VERSION 5.8 ;
BUSBITCHARS "[]" ;
DIVIDERCHAR "/" ;
UNITS
    DATABASE MICRONS 1000 ;
END UNITS

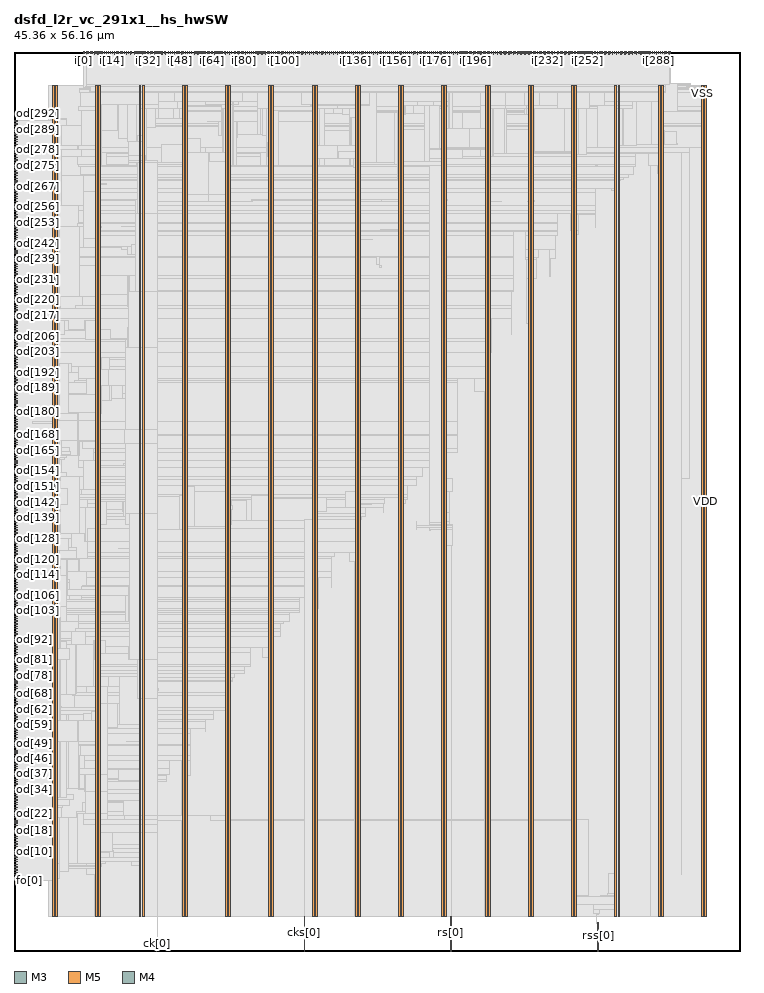
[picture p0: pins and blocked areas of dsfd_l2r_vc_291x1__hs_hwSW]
MACRO dsfd_l2r_vc_291x1__hs_hwSW
  FOREIGN dsfd_l2r_vc_291x1__hs_hwSW 0 0 ;
  CLASS BLOCK ;
  SIZE 45.36 BY 56.16 ;
  PIN ck[0]
    DIRECTION INPUT ;
    USE SIGNAL ;
    PORT
      LAYER M3 ;
        RECT  8.892 0 8.91 0.144 ;
    END
    PORT
      LAYER M3 ;
        RECT  8.892 0.108 8.91 0.52 ;
    END
  END ck[0]
  PIN cks[0]
    DIRECTION INPUT ;
    USE SIGNAL ;
    PORT
      LAYER M5 ;
        RECT  18.096 0 18.12 0.192 ;
    END
    PORT
      LAYER M5 ;
        RECT  18.096 0.144 18.12 2.137 ;
    END
  END cks[0]
  PIN fo[0]
    DIRECTION OUTPUT ;
    USE SIGNAL ;
    PORT
      LAYER M4 ;
        RECT  0 4.416 0.192 4.44 ;
    END
  END fo[0]
  PIN i[0]
    DIRECTION INPUT ;
    USE SIGNAL ;
    PORT
      LAYER M3 ;
        RECT  4.356 56.016 4.374 56.16 ;
    END
  END i[0]
  PIN i[100]
    DIRECTION INPUT ;
    USE SIGNAL ;
    PORT
      LAYER M3 ;
        RECT  16.812 56.016 16.83 56.16 ;
    END
  END i[100]
  PIN i[101]
    DIRECTION INPUT ;
    USE SIGNAL ;
    PORT
      LAYER M5 ;
        RECT  16.944 55.968 16.968 56.16 ;
    END
  END i[101]
  PIN i[102]
    DIRECTION INPUT ;
    USE SIGNAL ;
    PORT
      LAYER M3 ;
        RECT  17.064 56.016 17.082 56.16 ;
    END
  END i[102]
  PIN i[103]
    DIRECTION INPUT ;
    USE SIGNAL ;
    PORT
      LAYER M5 ;
        RECT  17.184 55.968 17.208 56.16 ;
    END
  END i[103]
  PIN i[104]
    DIRECTION INPUT ;
    USE SIGNAL ;
    PORT
      LAYER M3 ;
        RECT  17.316 56.016 17.334 56.16 ;
    END
  END i[104]
  PIN i[105]
    DIRECTION INPUT ;
    USE SIGNAL ;
    PORT
      LAYER M5 ;
        RECT  17.424 55.968 17.448 56.16 ;
    END
  END i[105]
  PIN i[106]
    DIRECTION INPUT ;
    USE SIGNAL ;
    PORT
      LAYER M3 ;
        RECT  17.568 56.016 17.586 56.16 ;
    END
  END i[106]
  PIN i[107]
    DIRECTION INPUT ;
    USE SIGNAL ;
    PORT
      LAYER M5 ;
        RECT  17.712 55.968 17.736 56.16 ;
    END
  END i[107]
  PIN i[108]
    DIRECTION INPUT ;
    USE SIGNAL ;
    PORT
      LAYER M3 ;
        RECT  17.82 56.016 17.838 56.16 ;
    END
  END i[108]
  PIN i[109]
    DIRECTION INPUT ;
    USE SIGNAL ;
    PORT
      LAYER M5 ;
        RECT  17.952 55.968 17.976 56.16 ;
    END
  END i[109]
  PIN i[10]
    DIRECTION INPUT ;
    USE SIGNAL ;
    PORT
      LAYER M3 ;
        RECT  5.616 56.016 5.634 56.16 ;
    END
  END i[10]
  PIN i[110]
    DIRECTION INPUT ;
    USE SIGNAL ;
    PORT
      LAYER M3 ;
        RECT  18.072 56.016 18.09 56.16 ;
    END
  END i[110]
  PIN i[111]
    DIRECTION INPUT ;
    USE SIGNAL ;
    PORT
      LAYER M5 ;
        RECT  18.192 55.968 18.216 56.16 ;
    END
  END i[111]
  PIN i[112]
    DIRECTION INPUT ;
    USE SIGNAL ;
    PORT
      LAYER M3 ;
        RECT  18.324 56.016 18.342 56.16 ;
    END
  END i[112]
  PIN i[113]
    DIRECTION INPUT ;
    USE SIGNAL ;
    PORT
      LAYER M5 ;
        RECT  18.432 55.968 18.456 56.16 ;
    END
  END i[113]
  PIN i[114]
    DIRECTION INPUT ;
    USE SIGNAL ;
    PORT
      LAYER M3 ;
        RECT  18.576 56.016 18.594 56.16 ;
    END
  END i[114]
  PIN i[115]
    DIRECTION INPUT ;
    USE SIGNAL ;
    PORT
      LAYER M5 ;
        RECT  18.672 55.968 18.696 56.16 ;
    END
  END i[115]
  PIN i[116]
    DIRECTION INPUT ;
    USE SIGNAL ;
    PORT
      LAYER M3 ;
        RECT  18.828 56.016 18.846 56.16 ;
    END
  END i[116]
  PIN i[117]
    DIRECTION INPUT ;
    USE SIGNAL ;
    PORT
      LAYER M5 ;
        RECT  18.912 55.968 18.936 56.16 ;
    END
  END i[117]
  PIN i[118]
    DIRECTION INPUT ;
    USE SIGNAL ;
    PORT
      LAYER M3 ;
        RECT  19.044 56.016 19.062 56.16 ;
    END
  END i[118]
  PIN i[119]
    DIRECTION INPUT ;
    USE SIGNAL ;
    PORT
      LAYER M5 ;
        RECT  19.2 55.968 19.224 56.16 ;
    END
  END i[119]
  PIN i[11]
    DIRECTION INPUT ;
    USE SIGNAL ;
    PORT
      LAYER M5 ;
        RECT  5.76 55.968 5.784 56.16 ;
    END
  END i[11]
  PIN i[120]
    DIRECTION INPUT ;
    USE SIGNAL ;
    PORT
      LAYER M3 ;
        RECT  19.296 56.016 19.314 56.16 ;
    END
  END i[120]
  PIN i[121]
    DIRECTION INPUT ;
    USE SIGNAL ;
    PORT
      LAYER M5 ;
        RECT  19.44 55.968 19.464 56.16 ;
    END
  END i[121]
  PIN i[122]
    DIRECTION INPUT ;
    USE SIGNAL ;
    PORT
      LAYER M3 ;
        RECT  19.548 56.016 19.566 56.16 ;
    END
  END i[122]
  PIN i[123]
    DIRECTION INPUT ;
    USE SIGNAL ;
    PORT
      LAYER M5 ;
        RECT  19.68 55.968 19.704 56.16 ;
    END
  END i[123]
  PIN i[124]
    DIRECTION INPUT ;
    USE SIGNAL ;
    PORT
      LAYER M3 ;
        RECT  19.8 56.016 19.818 56.16 ;
    END
  END i[124]
  PIN i[125]
    DIRECTION INPUT ;
    USE SIGNAL ;
    PORT
      LAYER M5 ;
        RECT  19.92 55.968 19.944 56.16 ;
    END
  END i[125]
  PIN i[126]
    DIRECTION INPUT ;
    USE SIGNAL ;
    PORT
      LAYER M3 ;
        RECT  20.052 56.016 20.07 56.16 ;
    END
  END i[126]
  PIN i[127]
    DIRECTION INPUT ;
    USE SIGNAL ;
    PORT
      LAYER M5 ;
        RECT  20.16 55.968 20.184 56.16 ;
    END
  END i[127]
  PIN i[128]
    DIRECTION INPUT ;
    USE SIGNAL ;
    PORT
      LAYER M3 ;
        RECT  20.304 56.016 20.322 56.16 ;
    END
  END i[128]
  PIN i[129]
    DIRECTION INPUT ;
    USE SIGNAL ;
    PORT
      LAYER M5 ;
        RECT  20.448 55.968 20.472 56.16 ;
    END
  END i[129]
  PIN i[12]
    DIRECTION INPUT ;
    USE SIGNAL ;
    PORT
      LAYER M3 ;
        RECT  5.868 56.016 5.886 56.16 ;
    END
  END i[12]
  PIN i[130]
    DIRECTION INPUT ;
    USE SIGNAL ;
    PORT
      LAYER M3 ;
        RECT  20.556 56.016 20.574 56.16 ;
    END
  END i[130]
  PIN i[131]
    DIRECTION INPUT ;
    USE SIGNAL ;
    PORT
      LAYER M5 ;
        RECT  20.688 55.968 20.712 56.16 ;
    END
  END i[131]
  PIN i[132]
    DIRECTION INPUT ;
    USE SIGNAL ;
    PORT
      LAYER M3 ;
        RECT  20.808 56.016 20.826 56.16 ;
    END
  END i[132]
  PIN i[133]
    DIRECTION INPUT ;
    USE SIGNAL ;
    PORT
      LAYER M5 ;
        RECT  20.928 55.968 20.952 56.16 ;
    END
  END i[133]
  PIN i[134]
    DIRECTION INPUT ;
    USE SIGNAL ;
    PORT
      LAYER M3 ;
        RECT  21.06 56.016 21.078 56.16 ;
    END
  END i[134]
  PIN i[135]
    DIRECTION INPUT ;
    USE SIGNAL ;
    PORT
      LAYER M5 ;
        RECT  21.168 55.968 21.192 56.16 ;
    END
  END i[135]
  PIN i[136]
    DIRECTION INPUT ;
    USE SIGNAL ;
    PORT
      LAYER M3 ;
        RECT  21.312 56.016 21.33 56.16 ;
    END
  END i[136]
  PIN i[137]
    DIRECTION INPUT ;
    USE SIGNAL ;
    PORT
      LAYER M5 ;
        RECT  21.408 55.968 21.432 56.16 ;
    END
  END i[137]
  PIN i[138]
    DIRECTION INPUT ;
    USE SIGNAL ;
    PORT
      LAYER M3 ;
        RECT  21.564 56.016 21.582 56.16 ;
    END
  END i[138]
  PIN i[139]
    DIRECTION INPUT ;
    USE SIGNAL ;
    PORT
      LAYER M5 ;
        RECT  21.696 55.968 21.72 56.16 ;
    END
  END i[139]
  PIN i[13]
    DIRECTION INPUT ;
    USE SIGNAL ;
    PORT
      LAYER M5 ;
        RECT  6 55.968 6.024 56.16 ;
    END
  END i[13]
  PIN i[140]
    DIRECTION INPUT ;
    USE SIGNAL ;
    PORT
      LAYER M3 ;
        RECT  21.816 56.016 21.834 56.16 ;
    END
  END i[140]
  PIN i[141]
    DIRECTION INPUT ;
    USE SIGNAL ;
    PORT
      LAYER M5 ;
        RECT  21.936 55.968 21.96 56.16 ;
    END
  END i[141]
  PIN i[142]
    DIRECTION INPUT ;
    USE SIGNAL ;
    PORT
      LAYER M3 ;
        RECT  22.032 56.016 22.05 56.16 ;
    END
  END i[142]
  PIN i[143]
    DIRECTION INPUT ;
    USE SIGNAL ;
    PORT
      LAYER M5 ;
        RECT  22.176 55.968 22.2 56.16 ;
    END
  END i[143]
  PIN i[144]
    DIRECTION INPUT ;
    USE SIGNAL ;
    PORT
      LAYER M3 ;
        RECT  22.284 56.016 22.302 56.16 ;
    END
  END i[144]
  PIN i[145]
    DIRECTION INPUT ;
    USE SIGNAL ;
    PORT
      LAYER M5 ;
        RECT  22.416 55.968 22.44 56.16 ;
    END
  END i[145]
  PIN i[146]
    DIRECTION INPUT ;
    USE SIGNAL ;
    PORT
      LAYER M3 ;
        RECT  22.536 56.016 22.554 56.16 ;
    END
  END i[146]
  PIN i[147]
    DIRECTION INPUT ;
    USE SIGNAL ;
    PORT
      LAYER M5 ;
        RECT  22.656 55.968 22.68 56.16 ;
    END
  END i[147]
  PIN i[148]
    DIRECTION INPUT ;
    USE SIGNAL ;
    PORT
      LAYER M3 ;
        RECT  22.788 56.016 22.806 56.16 ;
    END
  END i[148]
  PIN i[149]
    DIRECTION INPUT ;
    USE SIGNAL ;
    PORT
      LAYER M5 ;
        RECT  22.896 55.968 22.92 56.16 ;
    END
  END i[149]
  PIN i[14]
    DIRECTION INPUT ;
    USE SIGNAL ;
    PORT
      LAYER M3 ;
        RECT  6.12 56.016 6.138 56.16 ;
    END
  END i[14]
  PIN i[150]
    DIRECTION INPUT ;
    USE SIGNAL ;
    PORT
      LAYER M3 ;
        RECT  23.04 56.016 23.058 56.16 ;
    END
  END i[150]
  PIN i[151]
    DIRECTION INPUT ;
    USE SIGNAL ;
    PORT
      LAYER M5 ;
        RECT  23.184 55.968 23.208 56.16 ;
    END
  END i[151]
  PIN i[152]
    DIRECTION INPUT ;
    USE SIGNAL ;
    PORT
      LAYER M3 ;
        RECT  23.292 56.016 23.31 56.16 ;
    END
  END i[152]
  PIN i[153]
    DIRECTION INPUT ;
    USE SIGNAL ;
    PORT
      LAYER M5 ;
        RECT  23.424 55.968 23.448 56.16 ;
    END
  END i[153]
  PIN i[154]
    DIRECTION INPUT ;
    USE SIGNAL ;
    PORT
      LAYER M3 ;
        RECT  23.544 56.016 23.562 56.16 ;
    END
  END i[154]
  PIN i[155]
    DIRECTION INPUT ;
    USE SIGNAL ;
    PORT
      LAYER M5 ;
        RECT  23.664 55.968 23.688 56.16 ;
    END
  END i[155]
  PIN i[156]
    DIRECTION INPUT ;
    USE SIGNAL ;
    PORT
      LAYER M3 ;
        RECT  23.796 56.016 23.814 56.16 ;
    END
  END i[156]
  PIN i[157]
    DIRECTION INPUT ;
    USE SIGNAL ;
    PORT
      LAYER M5 ;
        RECT  23.904 55.968 23.928 56.16 ;
    END
  END i[157]
  PIN i[158]
    DIRECTION INPUT ;
    USE SIGNAL ;
    PORT
      LAYER M3 ;
        RECT  24.048 56.016 24.066 56.16 ;
    END
  END i[158]
  PIN i[159]
    DIRECTION INPUT ;
    USE SIGNAL ;
    PORT
      LAYER M5 ;
        RECT  24.144 55.968 24.168 56.16 ;
    END
  END i[159]
  PIN i[15]
    DIRECTION INPUT ;
    USE SIGNAL ;
    PORT
      LAYER M5 ;
        RECT  6.24 55.968 6.264 56.16 ;
    END
  END i[15]
  PIN i[160]
    DIRECTION INPUT ;
    USE SIGNAL ;
    PORT
      LAYER M3 ;
        RECT  24.3 56.016 24.318 56.16 ;
    END
  END i[160]
  PIN i[161]
    DIRECTION INPUT ;
    USE SIGNAL ;
    PORT
      LAYER M5 ;
        RECT  24.432 55.968 24.456 56.16 ;
    END
  END i[161]
  PIN i[162]
    DIRECTION INPUT ;
    USE SIGNAL ;
    PORT
      LAYER M3 ;
        RECT  24.552 56.016 24.57 56.16 ;
    END
  END i[162]
  PIN i[163]
    DIRECTION INPUT ;
    USE SIGNAL ;
    PORT
      LAYER M5 ;
        RECT  24.672 55.968 24.696 56.16 ;
    END
  END i[163]
  PIN i[164]
    DIRECTION INPUT ;
    USE SIGNAL ;
    PORT
      LAYER M3 ;
        RECT  24.804 56.016 24.822 56.16 ;
    END
  END i[164]
  PIN i[165]
    DIRECTION INPUT ;
    USE SIGNAL ;
    PORT
      LAYER M5 ;
        RECT  24.912 55.968 24.936 56.16 ;
    END
  END i[165]
  PIN i[166]
    DIRECTION INPUT ;
    USE SIGNAL ;
    PORT
      LAYER M3 ;
        RECT  25.02 56.016 25.038 56.16 ;
    END
  END i[166]
  PIN i[167]
    DIRECTION INPUT ;
    USE SIGNAL ;
    PORT
      LAYER M5 ;
        RECT  25.152 55.968 25.176 56.16 ;
    END
  END i[167]
  PIN i[168]
    DIRECTION INPUT ;
    USE SIGNAL ;
    PORT
      LAYER M3 ;
        RECT  25.272 56.016 25.29 56.16 ;
    END
  END i[168]
  PIN i[169]
    DIRECTION INPUT ;
    USE SIGNAL ;
    PORT
      LAYER M5 ;
        RECT  25.392 55.968 25.416 56.16 ;
    END
  END i[169]
  PIN i[16]
    DIRECTION INPUT ;
    USE SIGNAL ;
    PORT
      LAYER M3 ;
        RECT  6.372 56.016 6.39 56.16 ;
    END
  END i[16]
  PIN i[170]
    DIRECTION INPUT ;
    USE SIGNAL ;
    PORT
      LAYER M3 ;
        RECT  25.524 56.016 25.542 56.16 ;
    END
  END i[170]
  PIN i[171]
    DIRECTION INPUT ;
    USE SIGNAL ;
    PORT
      LAYER M5 ;
        RECT  25.632 55.968 25.656 56.16 ;
    END
  END i[171]
  PIN i[172]
    DIRECTION INPUT ;
    USE SIGNAL ;
    PORT
      LAYER M3 ;
        RECT  25.776 56.016 25.794 56.16 ;
    END
  END i[172]
  PIN i[173]
    DIRECTION INPUT ;
    USE SIGNAL ;
    PORT
      LAYER M5 ;
        RECT  25.92 55.968 25.944 56.16 ;
    END
  END i[173]
  PIN i[174]
    DIRECTION INPUT ;
    USE SIGNAL ;
    PORT
      LAYER M3 ;
        RECT  26.028 56.016 26.046 56.16 ;
    END
  END i[174]
  PIN i[175]
    DIRECTION INPUT ;
    USE SIGNAL ;
    PORT
      LAYER M5 ;
        RECT  26.16 55.968 26.184 56.16 ;
    END
  END i[175]
  PIN i[176]
    DIRECTION INPUT ;
    USE SIGNAL ;
    PORT
      LAYER M3 ;
        RECT  26.28 56.016 26.298 56.16 ;
    END
  END i[176]
  PIN i[177]
    DIRECTION INPUT ;
    USE SIGNAL ;
    PORT
      LAYER M5 ;
        RECT  26.4 55.968 26.424 56.16 ;
    END
  END i[177]
  PIN i[178]
    DIRECTION INPUT ;
    USE SIGNAL ;
    PORT
      LAYER M3 ;
        RECT  26.532 56.016 26.55 56.16 ;
    END
  END i[178]
  PIN i[179]
    DIRECTION INPUT ;
    USE SIGNAL ;
    PORT
      LAYER M5 ;
        RECT  26.64 55.968 26.664 56.16 ;
    END
  END i[179]
  PIN i[17]
    DIRECTION INPUT ;
    USE SIGNAL ;
    PORT
      LAYER M5 ;
        RECT  6.48 55.968 6.504 56.16 ;
    END
  END i[17]
  PIN i[180]
    DIRECTION INPUT ;
    USE SIGNAL ;
    PORT
      LAYER M3 ;
        RECT  26.784 56.016 26.802 56.16 ;
    END
  END i[180]
  PIN i[181]
    DIRECTION INPUT ;
    USE SIGNAL ;
    PORT
      LAYER M5 ;
        RECT  26.88 55.968 26.904 56.16 ;
    END
  END i[181]
  PIN i[182]
    DIRECTION INPUT ;
    USE SIGNAL ;
    PORT
      LAYER M3 ;
        RECT  27.036 56.016 27.054 56.16 ;
    END
  END i[182]
  PIN i[183]
    DIRECTION INPUT ;
    USE SIGNAL ;
    PORT
      LAYER M5 ;
        RECT  27.168 55.968 27.192 56.16 ;
    END
  END i[183]
  PIN i[184]
    DIRECTION INPUT ;
    USE SIGNAL ;
    PORT
      LAYER M3 ;
        RECT  27.288 56.016 27.306 56.16 ;
    END
  END i[184]
  PIN i[185]
    DIRECTION INPUT ;
    USE SIGNAL ;
    PORT
      LAYER M5 ;
        RECT  27.408 55.968 27.432 56.16 ;
    END
  END i[185]
  PIN i[186]
    DIRECTION INPUT ;
    USE SIGNAL ;
    PORT
      LAYER M3 ;
        RECT  27.54 56.016 27.558 56.16 ;
    END
  END i[186]
  PIN i[187]
    DIRECTION INPUT ;
    USE SIGNAL ;
    PORT
      LAYER M5 ;
        RECT  27.648 55.968 27.672 56.16 ;
    END
  END i[187]
  PIN i[188]
    DIRECTION INPUT ;
    USE SIGNAL ;
    PORT
      LAYER M3 ;
        RECT  27.792 56.016 27.81 56.16 ;
    END
  END i[188]
  PIN i[189]
    DIRECTION INPUT ;
    USE SIGNAL ;
    PORT
      LAYER M5 ;
        RECT  27.888 55.968 27.912 56.16 ;
    END
  END i[189]
  PIN i[18]
    DIRECTION INPUT ;
    USE SIGNAL ;
    PORT
      LAYER M3 ;
        RECT  6.624 56.016 6.642 56.16 ;
    END
  END i[18]
  PIN i[190]
    DIRECTION INPUT ;
    USE SIGNAL ;
    PORT
      LAYER M3 ;
        RECT  28.008 56.016 28.026 56.16 ;
    END
  END i[190]
  PIN i[191]
    DIRECTION INPUT ;
    USE SIGNAL ;
    PORT
      LAYER M5 ;
        RECT  28.128 55.968 28.152 56.16 ;
    END
  END i[191]
  PIN i[192]
    DIRECTION INPUT ;
    USE SIGNAL ;
    PORT
      LAYER M3 ;
        RECT  28.26 56.016 28.278 56.16 ;
    END
  END i[192]
  PIN i[193]
    DIRECTION INPUT ;
    USE SIGNAL ;
    PORT
      LAYER M5 ;
        RECT  28.416 55.968 28.44 56.16 ;
    END
  END i[193]
  PIN i[194]
    DIRECTION INPUT ;
    USE SIGNAL ;
    PORT
      LAYER M3 ;
        RECT  28.512 56.016 28.53 56.16 ;
    END
  END i[194]
  PIN i[195]
    DIRECTION INPUT ;
    USE SIGNAL ;
    PORT
      LAYER M5 ;
        RECT  28.656 55.968 28.68 56.16 ;
    END
  END i[195]
  PIN i[196]
    DIRECTION INPUT ;
    USE SIGNAL ;
    PORT
      LAYER M3 ;
        RECT  28.764 56.016 28.782 56.16 ;
    END
  END i[196]
  PIN i[197]
    DIRECTION INPUT ;
    USE SIGNAL ;
    PORT
      LAYER M5 ;
        RECT  28.896 55.968 28.92 56.16 ;
    END
  END i[197]
  PIN i[198]
    DIRECTION INPUT ;
    USE SIGNAL ;
    PORT
      LAYER M3 ;
        RECT  29.016 56.016 29.034 56.16 ;
    END
  END i[198]
  PIN i[199]
    DIRECTION INPUT ;
    USE SIGNAL ;
    PORT
      LAYER M5 ;
        RECT  29.136 55.968 29.16 56.16 ;
    END
  END i[199]
  PIN i[19]
    DIRECTION INPUT ;
    USE SIGNAL ;
    PORT
      LAYER M5 ;
        RECT  6.72 55.968 6.744 56.16 ;
    END
  END i[19]
  PIN i[1]
    DIRECTION INPUT ;
    USE SIGNAL ;
    PORT
      LAYER M5 ;
        RECT  4.512 55.968 4.536 56.16 ;
    END
  END i[1]
  PIN i[200]
    DIRECTION INPUT ;
    USE SIGNAL ;
    PORT
      LAYER M3 ;
        RECT  29.268 56.016 29.286 56.16 ;
    END
  END i[200]
  PIN i[201]
    DIRECTION INPUT ;
    USE SIGNAL ;
    PORT
      LAYER M5 ;
        RECT  29.376 55.968 29.4 56.16 ;
    END
  END i[201]
  PIN i[202]
    DIRECTION INPUT ;
    USE SIGNAL ;
    PORT
      LAYER M3 ;
        RECT  29.52 56.016 29.538 56.16 ;
    END
  END i[202]
  PIN i[203]
    DIRECTION INPUT ;
    USE SIGNAL ;
    PORT
      LAYER M5 ;
        RECT  29.616 55.968 29.64 56.16 ;
    END
  END i[203]
  PIN i[204]
    DIRECTION INPUT ;
    USE SIGNAL ;
    PORT
      LAYER M3 ;
        RECT  29.772 56.016 29.79 56.16 ;
    END
  END i[204]
  PIN i[205]
    DIRECTION INPUT ;
    USE SIGNAL ;
    PORT
      LAYER M5 ;
        RECT  29.904 55.968 29.928 56.16 ;
    END
  END i[205]
  PIN i[206]
    DIRECTION INPUT ;
    USE SIGNAL ;
    PORT
      LAYER M3 ;
        RECT  30.024 56.016 30.042 56.16 ;
    END
  END i[206]
  PIN i[207]
    DIRECTION INPUT ;
    USE SIGNAL ;
    PORT
      LAYER M5 ;
        RECT  30.144 55.968 30.168 56.16 ;
    END
  END i[207]
  PIN i[208]
    DIRECTION INPUT ;
    USE SIGNAL ;
    PORT
      LAYER M3 ;
        RECT  30.276 56.016 30.294 56.16 ;
    END
  END i[208]
  PIN i[209]
    DIRECTION INPUT ;
    USE SIGNAL ;
    PORT
      LAYER M5 ;
        RECT  30.384 55.968 30.408 56.16 ;
    END
  END i[209]
  PIN i[20]
    DIRECTION INPUT ;
    USE SIGNAL ;
    PORT
      LAYER M3 ;
        RECT  6.876 56.016 6.894 56.16 ;
    END
  END i[20]
  PIN i[210]
    DIRECTION INPUT ;
    USE SIGNAL ;
    PORT
      LAYER M3 ;
        RECT  30.528 56.016 30.546 56.16 ;
    END
  END i[210]
  PIN i[211]
    DIRECTION INPUT ;
    USE SIGNAL ;
    PORT
      LAYER M5 ;
        RECT  30.624 55.968 30.648 56.16 ;
    END
  END i[211]
  PIN i[212]
    DIRECTION INPUT ;
    USE SIGNAL ;
    PORT
      LAYER M3 ;
        RECT  30.744 56.016 30.762 56.16 ;
    END
  END i[212]
  PIN i[213]
    DIRECTION INPUT ;
    USE SIGNAL ;
    PORT
      LAYER M5 ;
        RECT  30.864 55.968 30.888 56.16 ;
    END
  END i[213]
  PIN i[214]
    DIRECTION INPUT ;
    USE SIGNAL ;
    PORT
      LAYER M3 ;
        RECT  30.996 56.016 31.014 56.16 ;
    END
  END i[214]
  PIN i[215]
    DIRECTION INPUT ;
    USE SIGNAL ;
    PORT
      LAYER M5 ;
        RECT  31.152 55.968 31.176 56.16 ;
    END
  END i[215]
  PIN i[216]
    DIRECTION INPUT ;
    USE SIGNAL ;
    PORT
      LAYER M3 ;
        RECT  31.248 56.016 31.266 56.16 ;
    END
  END i[216]
  PIN i[217]
    DIRECTION INPUT ;
    USE SIGNAL ;
    PORT
      LAYER M5 ;
        RECT  31.392 55.968 31.416 56.16 ;
    END
  END i[217]
  PIN i[218]
    DIRECTION INPUT ;
    USE SIGNAL ;
    PORT
      LAYER M3 ;
        RECT  31.5 56.016 31.518 56.16 ;
    END
  END i[218]
  PIN i[219]
    DIRECTION INPUT ;
    USE SIGNAL ;
    PORT
      LAYER M5 ;
        RECT  31.632 55.968 31.656 56.16 ;
    END
  END i[219]
  PIN i[21]
    DIRECTION INPUT ;
    USE SIGNAL ;
    PORT
      LAYER M5 ;
        RECT  7.008 55.968 7.032 56.16 ;
    END
  END i[21]
  PIN i[220]
    DIRECTION INPUT ;
    USE SIGNAL ;
    PORT
      LAYER M3 ;
        RECT  31.752 56.016 31.77 56.16 ;
    END
  END i[220]
  PIN i[221]
    DIRECTION INPUT ;
    USE SIGNAL ;
    PORT
      LAYER M5 ;
        RECT  31.872 55.968 31.896 56.16 ;
    END
  END i[221]
  PIN i[222]
    DIRECTION INPUT ;
    USE SIGNAL ;
    PORT
      LAYER M3 ;
        RECT  32.004 56.016 32.022 56.16 ;
    END
  END i[222]
  PIN i[223]
    DIRECTION INPUT ;
    USE SIGNAL ;
    PORT
      LAYER M5 ;
        RECT  32.112 55.968 32.136 56.16 ;
    END
  END i[223]
  PIN i[224]
    DIRECTION INPUT ;
    USE SIGNAL ;
    PORT
      LAYER M3 ;
        RECT  32.256 56.016 32.274 56.16 ;
    END
  END i[224]
  PIN i[225]
    DIRECTION INPUT ;
    USE SIGNAL ;
    PORT
      LAYER M5 ;
        RECT  32.4 55.968 32.424 56.16 ;
    END
  END i[225]
  PIN i[226]
    DIRECTION INPUT ;
    USE SIGNAL ;
    PORT
      LAYER M3 ;
        RECT  32.508 56.016 32.526 56.16 ;
    END
  END i[226]
  PIN i[227]
    DIRECTION INPUT ;
    USE SIGNAL ;
    PORT
      LAYER M5 ;
        RECT  32.64 55.968 32.664 56.16 ;
    END
  END i[227]
  PIN i[228]
    DIRECTION INPUT ;
    USE SIGNAL ;
    PORT
      LAYER M3 ;
        RECT  32.76 56.016 32.778 56.16 ;
    END
  END i[228]
  PIN i[229]
    DIRECTION INPUT ;
    USE SIGNAL ;
    PORT
      LAYER M5 ;
        RECT  32.88 55.968 32.904 56.16 ;
    END
  END i[229]
  PIN i[22]
    DIRECTION INPUT ;
    USE SIGNAL ;
    PORT
      LAYER M3 ;
        RECT  7.128 56.016 7.146 56.16 ;
    END
  END i[22]
  PIN i[230]
    DIRECTION INPUT ;
    USE SIGNAL ;
    PORT
      LAYER M3 ;
        RECT  33.012 56.016 33.03 56.16 ;
    END
  END i[230]
  PIN i[231]
    DIRECTION INPUT ;
    USE SIGNAL ;
    PORT
      LAYER M5 ;
        RECT  33.12 55.968 33.144 56.16 ;
    END
  END i[231]
  PIN i[232]
    DIRECTION INPUT ;
    USE SIGNAL ;
    PORT
      LAYER M3 ;
        RECT  33.264 56.016 33.282 56.16 ;
    END
  END i[232]
  PIN i[233]
    DIRECTION INPUT ;
    USE SIGNAL ;
    PORT
      LAYER M5 ;
        RECT  33.36 55.968 33.384 56.16 ;
    END
  END i[233]
  PIN i[234]
    DIRECTION INPUT ;
    USE SIGNAL ;
    PORT
      LAYER M3 ;
        RECT  33.516 56.016 33.534 56.16 ;
    END
  END i[234]
  PIN i[235]
    DIRECTION INPUT ;
    USE SIGNAL ;
    PORT
      LAYER M5 ;
        RECT  33.6 55.968 33.624 56.16 ;
    END
  END i[235]
  PIN i[236]
    DIRECTION INPUT ;
    USE SIGNAL ;
    PORT
      LAYER M3 ;
        RECT  33.732 56.016 33.75 56.16 ;
    END
  END i[236]
  PIN i[237]
    DIRECTION INPUT ;
    USE SIGNAL ;
    PORT
      LAYER M5 ;
        RECT  33.888 55.968 33.912 56.16 ;
    END
  END i[237]
  PIN i[238]
    DIRECTION INPUT ;
    USE SIGNAL ;
    PORT
      LAYER M3 ;
        RECT  33.984 56.016 34.002 56.16 ;
    END
  END i[238]
  PIN i[239]
    DIRECTION INPUT ;
    USE SIGNAL ;
    PORT
      LAYER M5 ;
        RECT  34.128 55.968 34.152 56.16 ;
    END
  END i[239]
  PIN i[23]
    DIRECTION INPUT ;
    USE SIGNAL ;
    PORT
      LAYER M5 ;
        RECT  7.248 55.968 7.272 56.16 ;
    END
  END i[23]
  PIN i[240]
    DIRECTION INPUT ;
    USE SIGNAL ;
    PORT
      LAYER M3 ;
        RECT  34.236 56.016 34.254 56.16 ;
    END
  END i[240]
  PIN i[241]
    DIRECTION INPUT ;
    USE SIGNAL ;
    PORT
      LAYER M5 ;
        RECT  34.368 55.968 34.392 56.16 ;
    END
  END i[241]
  PIN i[242]
    DIRECTION INPUT ;
    USE SIGNAL ;
    PORT
      LAYER M3 ;
        RECT  34.488 56.016 34.506 56.16 ;
    END
  END i[242]
  PIN i[243]
    DIRECTION INPUT ;
    USE SIGNAL ;
    PORT
      LAYER M5 ;
        RECT  34.608 55.968 34.632 56.16 ;
    END
  END i[243]
  PIN i[244]
    DIRECTION INPUT ;
    USE SIGNAL ;
    PORT
      LAYER M3 ;
        RECT  34.74 56.016 34.758 56.16 ;
    END
  END i[244]
  PIN i[245]
    DIRECTION INPUT ;
    USE SIGNAL ;
    PORT
      LAYER M5 ;
        RECT  34.848 55.968 34.872 56.16 ;
    END
  END i[245]
  PIN i[246]
    DIRECTION INPUT ;
    USE SIGNAL ;
    PORT
      LAYER M3 ;
        RECT  34.992 56.016 35.01 56.16 ;
    END
  END i[246]
  PIN i[247]
    DIRECTION INPUT ;
    USE SIGNAL ;
    PORT
      LAYER M5 ;
        RECT  35.136 55.968 35.16 56.16 ;
    END
  END i[247]
  PIN i[248]
    DIRECTION INPUT ;
    USE SIGNAL ;
    PORT
      LAYER M3 ;
        RECT  35.244 56.016 35.262 56.16 ;
    END
  END i[248]
  PIN i[249]
    DIRECTION INPUT ;
    USE SIGNAL ;
    PORT
      LAYER M5 ;
        RECT  35.376 55.968 35.4 56.16 ;
    END
  END i[249]
  PIN i[24]
    DIRECTION INPUT ;
    USE SIGNAL ;
    PORT
      LAYER M3 ;
        RECT  7.344 56.016 7.362 56.16 ;
    END
  END i[24]
  PIN i[250]
    DIRECTION INPUT ;
    USE SIGNAL ;
    PORT
      LAYER M3 ;
        RECT  35.496 56.016 35.514 56.16 ;
    END
  END i[250]
  PIN i[251]
    DIRECTION INPUT ;
    USE SIGNAL ;
    PORT
      LAYER M5 ;
        RECT  35.616 55.968 35.64 56.16 ;
    END
  END i[251]
  PIN i[252]
    DIRECTION INPUT ;
    USE SIGNAL ;
    PORT
      LAYER M3 ;
        RECT  35.748 56.016 35.766 56.16 ;
    END
  END i[252]
  PIN i[253]
    DIRECTION INPUT ;
    USE SIGNAL ;
    PORT
      LAYER M5 ;
        RECT  35.856 55.968 35.88 56.16 ;
    END
  END i[253]
  PIN i[254]
    DIRECTION INPUT ;
    USE SIGNAL ;
    PORT
      LAYER M3 ;
        RECT  36 56.016 36.018 56.16 ;
    END
  END i[254]
  PIN i[255]
    DIRECTION INPUT ;
    USE SIGNAL ;
    PORT
      LAYER M5 ;
        RECT  36.096 55.968 36.12 56.16 ;
    END
  END i[255]
  PIN i[256]
    DIRECTION INPUT ;
    USE SIGNAL ;
    PORT
      LAYER M3 ;
        RECT  36.252 56.016 36.27 56.16 ;
    END
  END i[256]
  PIN i[257]
    DIRECTION INPUT ;
    USE SIGNAL ;
    PORT
      LAYER M5 ;
        RECT  36.384 55.968 36.408 56.16 ;
    END
  END i[257]
  PIN i[258]
    DIRECTION INPUT ;
    USE SIGNAL ;
    PORT
      LAYER M3 ;
        RECT  36.504 56.016 36.522 56.16 ;
    END
  END i[258]
  PIN i[259]
    DIRECTION INPUT ;
    USE SIGNAL ;
    PORT
      LAYER M5 ;
        RECT  36.624 55.968 36.648 56.16 ;
    END
  END i[259]
  PIN i[25]
    DIRECTION INPUT ;
    USE SIGNAL ;
    PORT
      LAYER M5 ;
        RECT  7.488 55.968 7.512 56.16 ;
    END
  END i[25]
  PIN i[260]
    DIRECTION INPUT ;
    USE SIGNAL ;
    PORT
      LAYER M3 ;
        RECT  36.72 56.016 36.738 56.16 ;
    END
  END i[260]
  PIN i[261]
    DIRECTION INPUT ;
    USE SIGNAL ;
    PORT
      LAYER M5 ;
        RECT  36.864 55.968 36.888 56.16 ;
    END
  END i[261]
  PIN i[262]
    DIRECTION INPUT ;
    USE SIGNAL ;
    PORT
      LAYER M3 ;
        RECT  36.972 56.016 36.99 56.16 ;
    END
  END i[262]
  PIN i[263]
    DIRECTION INPUT ;
    USE SIGNAL ;
    PORT
      LAYER M5 ;
        RECT  37.104 55.968 37.128 56.16 ;
    END
  END i[263]
  PIN i[264]
    DIRECTION INPUT ;
    USE SIGNAL ;
    PORT
      LAYER M3 ;
        RECT  37.224 56.016 37.242 56.16 ;
    END
  END i[264]
  PIN i[265]
    DIRECTION INPUT ;
    USE SIGNAL ;
    PORT
      LAYER M5 ;
        RECT  37.344 55.968 37.368 56.16 ;
    END
  END i[265]
  PIN i[266]
    DIRECTION INPUT ;
    USE SIGNAL ;
    PORT
      LAYER M3 ;
        RECT  37.476 56.016 37.494 56.16 ;
    END
  END i[266]
  PIN i[267]
    DIRECTION INPUT ;
    USE SIGNAL ;
    PORT
      LAYER M5 ;
        RECT  37.584 55.968 37.608 56.16 ;
    END
  END i[267]
  PIN i[268]
    DIRECTION INPUT ;
    USE SIGNAL ;
    PORT
      LAYER M3 ;
        RECT  37.728 56.016 37.746 56.16 ;
    END
  END i[268]
  PIN i[269]
    DIRECTION INPUT ;
    USE SIGNAL ;
    PORT
      LAYER M5 ;
        RECT  37.872 55.968 37.896 56.16 ;
    END
  END i[269]
  PIN i[26]
    DIRECTION INPUT ;
    USE SIGNAL ;
    PORT
      LAYER M3 ;
        RECT  7.596 56.016 7.614 56.16 ;
    END
  END i[26]
  PIN i[270]
    DIRECTION INPUT ;
    USE SIGNAL ;
    PORT
      LAYER M3 ;
        RECT  37.98 56.016 37.998 56.16 ;
    END
  END i[270]
  PIN i[271]
    DIRECTION INPUT ;
    USE SIGNAL ;
    PORT
      LAYER M5 ;
        RECT  38.112 55.968 38.136 56.16 ;
    END
  END i[271]
  PIN i[272]
    DIRECTION INPUT ;
    USE SIGNAL ;
    PORT
      LAYER M3 ;
        RECT  38.232 56.016 38.25 56.16 ;
    END
  END i[272]
  PIN i[273]
    DIRECTION INPUT ;
    USE SIGNAL ;
    PORT
      LAYER M5 ;
        RECT  38.352 55.968 38.376 56.16 ;
    END
  END i[273]
  PIN i[274]
    DIRECTION INPUT ;
    USE SIGNAL ;
    PORT
      LAYER M3 ;
        RECT  38.484 56.016 38.502 56.16 ;
    END
  END i[274]
  PIN i[275]
    DIRECTION INPUT ;
    USE SIGNAL ;
    PORT
      LAYER M5 ;
        RECT  38.592 55.968 38.616 56.16 ;
    END
  END i[275]
  PIN i[276]
    DIRECTION INPUT ;
    USE SIGNAL ;
    PORT
      LAYER M3 ;
        RECT  38.736 56.016 38.754 56.16 ;
    END
  END i[276]
  PIN i[277]
    DIRECTION INPUT ;
    USE SIGNAL ;
    PORT
      LAYER M5 ;
        RECT  38.832 55.968 38.856 56.16 ;
    END
  END i[277]
  PIN i[278]
    DIRECTION INPUT ;
    USE SIGNAL ;
    PORT
      LAYER M3 ;
        RECT  38.988 56.016 39.006 56.16 ;
    END
  END i[278]
  PIN i[279]
    DIRECTION INPUT ;
    USE SIGNAL ;
    PORT
      LAYER M5 ;
        RECT  39.12 55.968 39.144 56.16 ;
    END
  END i[279]
  PIN i[27]
    DIRECTION INPUT ;
    USE SIGNAL ;
    PORT
      LAYER M5 ;
        RECT  7.728 55.968 7.752 56.16 ;
    END
  END i[27]
  PIN i[280]
    DIRECTION INPUT ;
    USE SIGNAL ;
    PORT
      LAYER M3 ;
        RECT  39.24 56.016 39.258 56.16 ;
    END
  END i[280]
  PIN i[281]
    DIRECTION INPUT ;
    USE SIGNAL ;
    PORT
      LAYER M5 ;
        RECT  39.36 55.968 39.384 56.16 ;
    END
  END i[281]
  PIN i[282]
    DIRECTION INPUT ;
    USE SIGNAL ;
    PORT
      LAYER M3 ;
        RECT  39.492 56.016 39.51 56.16 ;
    END
  END i[282]
  PIN i[283]
    DIRECTION INPUT ;
    USE SIGNAL ;
    PORT
      LAYER M5 ;
        RECT  39.6 55.968 39.624 56.16 ;
    END
  END i[283]
  PIN i[284]
    DIRECTION INPUT ;
    USE SIGNAL ;
    PORT
      LAYER M3 ;
        RECT  39.708 56.016 39.726 56.16 ;
    END
  END i[284]
  PIN i[285]
    DIRECTION INPUT ;
    USE SIGNAL ;
    PORT
      LAYER M5 ;
        RECT  39.84 55.968 39.864 56.16 ;
    END
  END i[285]
  PIN i[286]
    DIRECTION INPUT ;
    USE SIGNAL ;
    PORT
      LAYER M3 ;
        RECT  39.96 56.016 39.978 56.16 ;
    END
  END i[286]
  PIN i[287]
    DIRECTION INPUT ;
    USE SIGNAL ;
    PORT
      LAYER M5 ;
        RECT  40.08 55.968 40.104 56.16 ;
    END
  END i[287]
  PIN i[288]
    DIRECTION INPUT ;
    USE SIGNAL ;
    PORT
      LAYER M3 ;
        RECT  40.212 56.016 40.23 56.16 ;
    END
  END i[288]
  PIN i[289]
    DIRECTION INPUT ;
    USE SIGNAL ;
    PORT
      LAYER M5 ;
        RECT  40.32 55.968 40.344 56.16 ;
    END
  END i[289]
  PIN i[28]
    DIRECTION INPUT ;
    USE SIGNAL ;
    PORT
      LAYER M3 ;
        RECT  7.848 56.016 7.866 56.16 ;
    END
  END i[28]
  PIN i[290]
    DIRECTION INPUT ;
    USE SIGNAL ;
    PORT
      LAYER M3 ;
        RECT  40.464 56.016 40.482 56.16 ;
    END
  END i[290]
  PIN i[291]
    DIRECTION INPUT ;
    USE SIGNAL ;
    PORT
      LAYER M5 ;
        RECT  40.608 55.968 40.632 56.16 ;
    END
  END i[291]
  PIN i[29]
    DIRECTION INPUT ;
    USE SIGNAL ;
    PORT
      LAYER M5 ;
        RECT  7.968 55.968 7.992 56.16 ;
    END
  END i[29]
  PIN i[2]
    DIRECTION INPUT ;
    USE SIGNAL ;
    PORT
      LAYER M3 ;
        RECT  4.608 56.016 4.626 56.16 ;
    END
  END i[2]
  PIN i[30]
    DIRECTION INPUT ;
    USE SIGNAL ;
    PORT
      LAYER M3 ;
        RECT  8.1 56.016 8.118 56.16 ;
    END
  END i[30]
  PIN i[31]
    DIRECTION INPUT ;
    USE SIGNAL ;
    PORT
      LAYER M5 ;
        RECT  8.208 55.968 8.232 56.16 ;
    END
  END i[31]
  PIN i[32]
    DIRECTION INPUT ;
    USE SIGNAL ;
    PORT
      LAYER M3 ;
        RECT  8.352 56.016 8.37 56.16 ;
    END
  END i[32]
  PIN i[33]
    DIRECTION INPUT ;
    USE SIGNAL ;
    PORT
      LAYER M5 ;
        RECT  8.496 55.968 8.52 56.16 ;
    END
  END i[33]
  PIN i[34]
    DIRECTION INPUT ;
    USE SIGNAL ;
    PORT
      LAYER M3 ;
        RECT  8.604 56.016 8.622 56.16 ;
    END
  END i[34]
  PIN i[35]
    DIRECTION INPUT ;
    USE SIGNAL ;
    PORT
      LAYER M5 ;
        RECT  8.736 55.968 8.76 56.16 ;
    END
  END i[35]
  PIN i[36]
    DIRECTION INPUT ;
    USE SIGNAL ;
    PORT
      LAYER M3 ;
        RECT  8.856 56.016 8.874 56.16 ;
    END
  END i[36]
  PIN i[37]
    DIRECTION INPUT ;
    USE SIGNAL ;
    PORT
      LAYER M5 ;
        RECT  8.976 55.968 9 56.16 ;
    END
  END i[37]
  PIN i[38]
    DIRECTION INPUT ;
    USE SIGNAL ;
    PORT
      LAYER M3 ;
        RECT  9.108 56.016 9.126 56.16 ;
    END
  END i[38]
  PIN i[39]
    DIRECTION INPUT ;
    USE SIGNAL ;
    PORT
      LAYER M5 ;
        RECT  9.216 55.968 9.24 56.16 ;
    END
  END i[39]
  PIN i[3]
    DIRECTION INPUT ;
    USE SIGNAL ;
    PORT
      LAYER M5 ;
        RECT  4.752 55.968 4.776 56.16 ;
    END
  END i[3]
  PIN i[40]
    DIRECTION INPUT ;
    USE SIGNAL ;
    PORT
      LAYER M3 ;
        RECT  9.36 56.016 9.378 56.16 ;
    END
  END i[40]
  PIN i[41]
    DIRECTION INPUT ;
    USE SIGNAL ;
    PORT
      LAYER M5 ;
        RECT  9.456 55.968 9.48 56.16 ;
    END
  END i[41]
  PIN i[42]
    DIRECTION INPUT ;
    USE SIGNAL ;
    PORT
      LAYER M3 ;
        RECT  9.612 56.016 9.63 56.16 ;
    END
  END i[42]
  PIN i[43]
    DIRECTION INPUT ;
    USE SIGNAL ;
    PORT
      LAYER M5 ;
        RECT  9.744 55.968 9.768 56.16 ;
    END
  END i[43]
  PIN i[44]
    DIRECTION INPUT ;
    USE SIGNAL ;
    PORT
      LAYER M3 ;
        RECT  9.864 56.016 9.882 56.16 ;
    END
  END i[44]
  PIN i[45]
    DIRECTION INPUT ;
    USE SIGNAL ;
    PORT
      LAYER M5 ;
        RECT  9.984 55.968 10.008 56.16 ;
    END
  END i[45]
  PIN i[46]
    DIRECTION INPUT ;
    USE SIGNAL ;
    PORT
      LAYER M3 ;
        RECT  10.116 56.016 10.134 56.16 ;
    END
  END i[46]
  PIN i[47]
    DIRECTION INPUT ;
    USE SIGNAL ;
    PORT
      LAYER M5 ;
        RECT  10.224 55.968 10.248 56.16 ;
    END
  END i[47]
  PIN i[48]
    DIRECTION INPUT ;
    USE SIGNAL ;
    PORT
      LAYER M3 ;
        RECT  10.332 56.016 10.35 56.16 ;
    END
  END i[48]
  PIN i[49]
    DIRECTION INPUT ;
    USE SIGNAL ;
    PORT
      LAYER M5 ;
        RECT  10.464 55.968 10.488 56.16 ;
    END
  END i[49]
  PIN i[4]
    DIRECTION INPUT ;
    USE SIGNAL ;
    PORT
      LAYER M3 ;
        RECT  4.86 56.016 4.878 56.16 ;
    END
  END i[4]
  PIN i[50]
    DIRECTION INPUT ;
    USE SIGNAL ;
    PORT
      LAYER M3 ;
        RECT  10.584 56.016 10.602 56.16 ;
    END
  END i[50]
  PIN i[51]
    DIRECTION INPUT ;
    USE SIGNAL ;
    PORT
      LAYER M5 ;
        RECT  10.704 55.968 10.728 56.16 ;
    END
  END i[51]
  PIN i[52]
    DIRECTION INPUT ;
    USE SIGNAL ;
    PORT
      LAYER M3 ;
        RECT  10.836 56.016 10.854 56.16 ;
    END
  END i[52]
  PIN i[53]
    DIRECTION INPUT ;
    USE SIGNAL ;
    PORT
      LAYER M5 ;
        RECT  10.944 55.968 10.968 56.16 ;
    END
  END i[53]
  PIN i[54]
    DIRECTION INPUT ;
    USE SIGNAL ;
    PORT
      LAYER M3 ;
        RECT  11.088 56.016 11.106 56.16 ;
    END
  END i[54]
  PIN i[55]
    DIRECTION INPUT ;
    USE SIGNAL ;
    PORT
      LAYER M5 ;
        RECT  11.232 55.968 11.256 56.16 ;
    END
  END i[55]
  PIN i[56]
    DIRECTION INPUT ;
    USE SIGNAL ;
    PORT
      LAYER M3 ;
        RECT  11.34 56.016 11.358 56.16 ;
    END
  END i[56]
  PIN i[57]
    DIRECTION INPUT ;
    USE SIGNAL ;
    PORT
      LAYER M5 ;
        RECT  11.472 55.968 11.496 56.16 ;
    END
  END i[57]
  PIN i[58]
    DIRECTION INPUT ;
    USE SIGNAL ;
    PORT
      LAYER M3 ;
        RECT  11.592 56.016 11.61 56.16 ;
    END
  END i[58]
  PIN i[59]
    DIRECTION INPUT ;
    USE SIGNAL ;
    PORT
      LAYER M5 ;
        RECT  11.712 55.968 11.736 56.16 ;
    END
  END i[59]
  PIN i[5]
    DIRECTION INPUT ;
    USE SIGNAL ;
    PORT
      LAYER M5 ;
        RECT  4.992 55.968 5.016 56.16 ;
    END
  END i[5]
  PIN i[60]
    DIRECTION INPUT ;
    USE SIGNAL ;
    PORT
      LAYER M3 ;
        RECT  11.844 56.016 11.862 56.16 ;
    END
  END i[60]
  PIN i[61]
    DIRECTION INPUT ;
    USE SIGNAL ;
    PORT
      LAYER M5 ;
        RECT  11.952 55.968 11.976 56.16 ;
    END
  END i[61]
  PIN i[62]
    DIRECTION INPUT ;
    USE SIGNAL ;
    PORT
      LAYER M3 ;
        RECT  12.096 56.016 12.114 56.16 ;
    END
  END i[62]
  PIN i[63]
    DIRECTION INPUT ;
    USE SIGNAL ;
    PORT
      LAYER M5 ;
        RECT  12.192 55.968 12.216 56.16 ;
    END
  END i[63]
  PIN i[64]
    DIRECTION INPUT ;
    USE SIGNAL ;
    PORT
      LAYER M3 ;
        RECT  12.348 56.016 12.366 56.16 ;
    END
  END i[64]
  PIN i[65]
    DIRECTION INPUT ;
    USE SIGNAL ;
    PORT
      LAYER M5 ;
        RECT  12.48 55.968 12.504 56.16 ;
    END
  END i[65]
  PIN i[66]
    DIRECTION INPUT ;
    USE SIGNAL ;
    PORT
      LAYER M3 ;
        RECT  12.6 56.016 12.618 56.16 ;
    END
  END i[66]
  PIN i[67]
    DIRECTION INPUT ;
    USE SIGNAL ;
    PORT
      LAYER M5 ;
        RECT  12.72 55.968 12.744 56.16 ;
    END
  END i[67]
  PIN i[68]
    DIRECTION INPUT ;
    USE SIGNAL ;
    PORT
      LAYER M3 ;
        RECT  12.852 56.016 12.87 56.16 ;
    END
  END i[68]
  PIN i[69]
    DIRECTION INPUT ;
    USE SIGNAL ;
    PORT
      LAYER M5 ;
        RECT  12.96 55.968 12.984 56.16 ;
    END
  END i[69]
  PIN i[6]
    DIRECTION INPUT ;
    USE SIGNAL ;
    PORT
      LAYER M3 ;
        RECT  5.112 56.016 5.13 56.16 ;
    END
  END i[6]
  PIN i[70]
    DIRECTION INPUT ;
    USE SIGNAL ;
    PORT
      LAYER M3 ;
        RECT  13.104 56.016 13.122 56.16 ;
    END
  END i[70]
  PIN i[71]
    DIRECTION INPUT ;
    USE SIGNAL ;
    PORT
      LAYER M5 ;
        RECT  13.2 55.968 13.224 56.16 ;
    END
  END i[71]
  PIN i[72]
    DIRECTION INPUT ;
    USE SIGNAL ;
    PORT
      LAYER M3 ;
        RECT  13.32 56.016 13.338 56.16 ;
    END
  END i[72]
  PIN i[73]
    DIRECTION INPUT ;
    USE SIGNAL ;
    PORT
      LAYER M5 ;
        RECT  13.44 55.968 13.464 56.16 ;
    END
  END i[73]
  PIN i[74]
    DIRECTION INPUT ;
    USE SIGNAL ;
    PORT
      LAYER M3 ;
        RECT  13.572 56.016 13.59 56.16 ;
    END
  END i[74]
  PIN i[75]
    DIRECTION INPUT ;
    USE SIGNAL ;
    PORT
      LAYER M5 ;
        RECT  13.728 55.968 13.752 56.16 ;
    END
  END i[75]
  PIN i[76]
    DIRECTION INPUT ;
    USE SIGNAL ;
    PORT
      LAYER M3 ;
        RECT  13.824 56.016 13.842 56.16 ;
    END
  END i[76]
  PIN i[77]
    DIRECTION INPUT ;
    USE SIGNAL ;
    PORT
      LAYER M5 ;
        RECT  13.968 55.968 13.992 56.16 ;
    END
  END i[77]
  PIN i[78]
    DIRECTION INPUT ;
    USE SIGNAL ;
    PORT
      LAYER M3 ;
        RECT  14.076 56.016 14.094 56.16 ;
    END
  END i[78]
  PIN i[79]
    DIRECTION INPUT ;
    USE SIGNAL ;
    PORT
      LAYER M5 ;
        RECT  14.208 55.968 14.232 56.16 ;
    END
  END i[79]
  PIN i[7]
    DIRECTION INPUT ;
    USE SIGNAL ;
    PORT
      LAYER M5 ;
        RECT  5.232 55.968 5.256 56.16 ;
    END
  END i[7]
  PIN i[80]
    DIRECTION INPUT ;
    USE SIGNAL ;
    PORT
      LAYER M3 ;
        RECT  14.328 56.016 14.346 56.16 ;
    END
  END i[80]
  PIN i[81]
    DIRECTION INPUT ;
    USE SIGNAL ;
    PORT
      LAYER M5 ;
        RECT  14.448 55.968 14.472 56.16 ;
    END
  END i[81]
  PIN i[82]
    DIRECTION INPUT ;
    USE SIGNAL ;
    PORT
      LAYER M3 ;
        RECT  14.58 56.016 14.598 56.16 ;
    END
  END i[82]
  PIN i[83]
    DIRECTION INPUT ;
    USE SIGNAL ;
    PORT
      LAYER M5 ;
        RECT  14.688 55.968 14.712 56.16 ;
    END
  END i[83]
  PIN i[84]
    DIRECTION INPUT ;
    USE SIGNAL ;
    PORT
      LAYER M3 ;
        RECT  14.832 56.016 14.85 56.16 ;
    END
  END i[84]
  PIN i[85]
    DIRECTION INPUT ;
    USE SIGNAL ;
    PORT
      LAYER M5 ;
        RECT  14.928 55.968 14.952 56.16 ;
    END
  END i[85]
  PIN i[86]
    DIRECTION INPUT ;
    USE SIGNAL ;
    PORT
      LAYER M3 ;
        RECT  15.084 56.016 15.102 56.16 ;
    END
  END i[86]
  PIN i[87]
    DIRECTION INPUT ;
    USE SIGNAL ;
    PORT
      LAYER M5 ;
        RECT  15.216 55.968 15.24 56.16 ;
    END
  END i[87]
  PIN i[88]
    DIRECTION INPUT ;
    USE SIGNAL ;
    PORT
      LAYER M3 ;
        RECT  15.336 56.016 15.354 56.16 ;
    END
  END i[88]
  PIN i[89]
    DIRECTION INPUT ;
    USE SIGNAL ;
    PORT
      LAYER M5 ;
        RECT  15.456 55.968 15.48 56.16 ;
    END
  END i[89]
  PIN i[8]
    DIRECTION INPUT ;
    USE SIGNAL ;
    PORT
      LAYER M3 ;
        RECT  5.364 56.016 5.382 56.16 ;
    END
  END i[8]
  PIN i[90]
    DIRECTION INPUT ;
    USE SIGNAL ;
    PORT
      LAYER M3 ;
        RECT  15.588 56.016 15.606 56.16 ;
    END
  END i[90]
  PIN i[91]
    DIRECTION INPUT ;
    USE SIGNAL ;
    PORT
      LAYER M5 ;
        RECT  15.696 55.968 15.72 56.16 ;
    END
  END i[91]
  PIN i[92]
    DIRECTION INPUT ;
    USE SIGNAL ;
    PORT
      LAYER M3 ;
        RECT  15.84 56.016 15.858 56.16 ;
    END
  END i[92]
  PIN i[93]
    DIRECTION INPUT ;
    USE SIGNAL ;
    PORT
      LAYER M5 ;
        RECT  15.936 55.968 15.96 56.16 ;
    END
  END i[93]
  PIN i[94]
    DIRECTION INPUT ;
    USE SIGNAL ;
    PORT
      LAYER M3 ;
        RECT  16.056 56.016 16.074 56.16 ;
    END
  END i[94]
  PIN i[95]
    DIRECTION INPUT ;
    USE SIGNAL ;
    PORT
      LAYER M5 ;
        RECT  16.176 55.968 16.2 56.16 ;
    END
  END i[95]
  PIN i[96]
    DIRECTION INPUT ;
    USE SIGNAL ;
    PORT
      LAYER M3 ;
        RECT  16.308 56.016 16.326 56.16 ;
    END
  END i[96]
  PIN i[97]
    DIRECTION INPUT ;
    USE SIGNAL ;
    PORT
      LAYER M5 ;
        RECT  16.464 55.968 16.488 56.16 ;
    END
  END i[97]
  PIN i[98]
    DIRECTION INPUT ;
    USE SIGNAL ;
    PORT
      LAYER M3 ;
        RECT  16.56 56.016 16.578 56.16 ;
    END
  END i[98]
  PIN i[99]
    DIRECTION INPUT ;
    USE SIGNAL ;
    PORT
      LAYER M5 ;
        RECT  16.704 55.968 16.728 56.16 ;
    END
  END i[99]
  PIN i[9]
    DIRECTION INPUT ;
    USE SIGNAL ;
    PORT
      LAYER M5 ;
        RECT  5.472 55.968 5.496 56.16 ;
    END
  END i[9]
  PIN od[0]
    DIRECTION OUTPUT ;
    USE SIGNAL ;
    PORT
      LAYER M4 ;
        RECT  0 4.56 0.192 4.584 ;
    END
  END od[0]
  PIN od[100]
    DIRECTION OUTPUT ;
    USE SIGNAL ;
    PORT
      LAYER M4 ;
        RECT  0 20.736 0.192 20.76 ;
    END
  END od[100]
  PIN od[101]
    DIRECTION OUTPUT ;
    USE SIGNAL ;
    PORT
      LAYER M4 ;
        RECT  0 20.88 0.192 20.904 ;
    END
  END od[101]
  PIN od[102]
    DIRECTION OUTPUT ;
    USE SIGNAL ;
    PORT
      LAYER M4 ;
        RECT  0 21.072 0.192 21.096 ;
    END
  END od[102]
  PIN od[103]
    DIRECTION OUTPUT ;
    USE SIGNAL ;
    PORT
      LAYER M4 ;
        RECT  0 21.216 0.192 21.24 ;
    END
  END od[103]
  PIN od[104]
    DIRECTION OUTPUT ;
    USE SIGNAL ;
    PORT
      LAYER M4 ;
        RECT  0 21.408 0.192 21.432 ;
    END
  END od[104]
  PIN od[105]
    DIRECTION OUTPUT ;
    USE SIGNAL ;
    PORT
      LAYER M4 ;
        RECT  0 21.552 0.192 21.576 ;
    END
  END od[105]
  PIN od[106]
    DIRECTION OUTPUT ;
    USE SIGNAL ;
    PORT
      LAYER M4 ;
        RECT  0 21.696 0.192 21.72 ;
    END
  END od[106]
  PIN od[107]
    DIRECTION OUTPUT ;
    USE SIGNAL ;
    PORT
      LAYER M4 ;
        RECT  0 21.888 0.192 21.912 ;
    END
  END od[107]
  PIN od[108]
    DIRECTION OUTPUT ;
    USE SIGNAL ;
    PORT
      LAYER M4 ;
        RECT  0 22.032 0.192 22.056 ;
    END
  END od[108]
  PIN od[109]
    DIRECTION OUTPUT ;
    USE SIGNAL ;
    PORT
      LAYER M4 ;
        RECT  0 22.176 0.192 22.2 ;
    END
  END od[109]
  PIN od[10]
    DIRECTION OUTPUT ;
    USE SIGNAL ;
    PORT
      LAYER M4 ;
        RECT  0 6.192 0.192 6.216 ;
    END
  END od[10]
  PIN od[110]
    DIRECTION OUTPUT ;
    USE SIGNAL ;
    PORT
      LAYER M4 ;
        RECT  0 22.368 0.192 22.392 ;
    END
  END od[110]
  PIN od[111]
    DIRECTION OUTPUT ;
    USE SIGNAL ;
    PORT
      LAYER M4 ;
        RECT  0 22.512 0.192 22.536 ;
    END
  END od[111]
  PIN od[112]
    DIRECTION OUTPUT ;
    USE SIGNAL ;
    PORT
      LAYER M4 ;
        RECT  0 22.656 0.192 22.68 ;
    END
  END od[112]
  PIN od[113]
    DIRECTION OUTPUT ;
    USE SIGNAL ;
    PORT
      LAYER M4 ;
        RECT  0 22.848 0.192 22.872 ;
    END
  END od[113]
  PIN od[114]
    DIRECTION OUTPUT ;
    USE SIGNAL ;
    PORT
      LAYER M4 ;
        RECT  0 22.992 0.192 23.016 ;
    END
  END od[114]
  PIN od[115]
    DIRECTION OUTPUT ;
    USE SIGNAL ;
    PORT
      LAYER M4 ;
        RECT  0 23.184 0.192 23.208 ;
    END
  END od[115]
  PIN od[116]
    DIRECTION OUTPUT ;
    USE SIGNAL ;
    PORT
      LAYER M4 ;
        RECT  0 23.328 0.192 23.352 ;
    END
  END od[116]
  PIN od[117]
    DIRECTION OUTPUT ;
    USE SIGNAL ;
    PORT
      LAYER M4 ;
        RECT  0 23.472 0.192 23.496 ;
    END
  END od[117]
  PIN od[118]
    DIRECTION OUTPUT ;
    USE SIGNAL ;
    PORT
      LAYER M4 ;
        RECT  0 23.664 0.192 23.688 ;
    END
  END od[118]
  PIN od[119]
    DIRECTION OUTPUT ;
    USE SIGNAL ;
    PORT
      LAYER M4 ;
        RECT  0 23.808 0.192 23.832 ;
    END
  END od[119]
  PIN od[11]
    DIRECTION OUTPUT ;
    USE SIGNAL ;
    PORT
      LAYER M4 ;
        RECT  0 6.336 0.192 6.36 ;
    END
  END od[11]
  PIN od[120]
    DIRECTION OUTPUT ;
    USE SIGNAL ;
    PORT
      LAYER M4 ;
        RECT  0 23.952 0.192 23.976 ;
    END
  END od[120]
  PIN od[121]
    DIRECTION OUTPUT ;
    USE SIGNAL ;
    PORT
      LAYER M4 ;
        RECT  0 24.144 0.192 24.168 ;
    END
  END od[121]
  PIN od[122]
    DIRECTION OUTPUT ;
    USE SIGNAL ;
    PORT
      LAYER M4 ;
        RECT  0 24.288 0.192 24.312 ;
    END
  END od[122]
  PIN od[123]
    DIRECTION OUTPUT ;
    USE SIGNAL ;
    PORT
      LAYER M4 ;
        RECT  0 24.432 0.192 24.456 ;
    END
  END od[123]
  PIN od[124]
    DIRECTION OUTPUT ;
    USE SIGNAL ;
    PORT
      LAYER M4 ;
        RECT  0 24.624 0.192 24.648 ;
    END
  END od[124]
  PIN od[125]
    DIRECTION OUTPUT ;
    USE SIGNAL ;
    PORT
      LAYER M4 ;
        RECT  0 24.768 0.192 24.792 ;
    END
  END od[125]
  PIN od[126]
    DIRECTION OUTPUT ;
    USE SIGNAL ;
    PORT
      LAYER M4 ;
        RECT  0 24.96 0.192 24.984 ;
    END
  END od[126]
  PIN od[127]
    DIRECTION OUTPUT ;
    USE SIGNAL ;
    PORT
      LAYER M4 ;
        RECT  0 25.104 0.192 25.128 ;
    END
  END od[127]
  PIN od[128]
    DIRECTION OUTPUT ;
    USE SIGNAL ;
    PORT
      LAYER M4 ;
        RECT  0 25.248 0.192 25.272 ;
    END
  END od[128]
  PIN od[129]
    DIRECTION OUTPUT ;
    USE SIGNAL ;
    PORT
      LAYER M4 ;
        RECT  0 25.44 0.192 25.464 ;
    END
  END od[129]
  PIN od[12]
    DIRECTION OUTPUT ;
    USE SIGNAL ;
    PORT
      LAYER M4 ;
        RECT  0 6.528 0.192 6.552 ;
    END
  END od[12]
  PIN od[130]
    DIRECTION OUTPUT ;
    USE SIGNAL ;
    PORT
      LAYER M4 ;
        RECT  0 25.584 0.192 25.608 ;
    END
  END od[130]
  PIN od[131]
    DIRECTION OUTPUT ;
    USE SIGNAL ;
    PORT
      LAYER M4 ;
        RECT  0 25.728 0.192 25.752 ;
    END
  END od[131]
  PIN od[132]
    DIRECTION OUTPUT ;
    USE SIGNAL ;
    PORT
      LAYER M4 ;
        RECT  0 25.92 0.192 25.944 ;
    END
  END od[132]
  PIN od[133]
    DIRECTION OUTPUT ;
    USE SIGNAL ;
    PORT
      LAYER M4 ;
        RECT  0 26.064 0.192 26.088 ;
    END
  END od[133]
  PIN od[134]
    DIRECTION OUTPUT ;
    USE SIGNAL ;
    PORT
      LAYER M4 ;
        RECT  0 26.256 0.192 26.28 ;
    END
  END od[134]
  PIN od[135]
    DIRECTION OUTPUT ;
    USE SIGNAL ;
    PORT
      LAYER M4 ;
        RECT  0 26.4 0.192 26.424 ;
    END
  END od[135]
  PIN od[136]
    DIRECTION OUTPUT ;
    USE SIGNAL ;
    PORT
      LAYER M4 ;
        RECT  0 26.544 0.192 26.568 ;
    END
  END od[136]
  PIN od[137]
    DIRECTION OUTPUT ;
    USE SIGNAL ;
    PORT
      LAYER M4 ;
        RECT  0 26.736 0.192 26.76 ;
    END
  END od[137]
  PIN od[138]
    DIRECTION OUTPUT ;
    USE SIGNAL ;
    PORT
      LAYER M4 ;
        RECT  0 26.88 0.192 26.904 ;
    END
  END od[138]
  PIN od[139]
    DIRECTION OUTPUT ;
    USE SIGNAL ;
    PORT
      LAYER M4 ;
        RECT  0 27.024 0.192 27.048 ;
    END
  END od[139]
  PIN od[13]
    DIRECTION OUTPUT ;
    USE SIGNAL ;
    PORT
      LAYER M4 ;
        RECT  0 6.672 0.192 6.696 ;
    END
  END od[13]
  PIN od[140]
    DIRECTION OUTPUT ;
    USE SIGNAL ;
    PORT
      LAYER M4 ;
        RECT  0 27.216 0.192 27.24 ;
    END
  END od[140]
  PIN od[141]
    DIRECTION OUTPUT ;
    USE SIGNAL ;
    PORT
      LAYER M4 ;
        RECT  0 27.36 0.192 27.384 ;
    END
  END od[141]
  PIN od[142]
    DIRECTION OUTPUT ;
    USE SIGNAL ;
    PORT
      LAYER M4 ;
        RECT  0 27.504 0.192 27.528 ;
    END
  END od[142]
  PIN od[143]
    DIRECTION OUTPUT ;
    USE SIGNAL ;
    PORT
      LAYER M4 ;
        RECT  0 27.696 0.192 27.72 ;
    END
  END od[143]
  PIN od[144]
    DIRECTION OUTPUT ;
    USE SIGNAL ;
    PORT
      LAYER M4 ;
        RECT  0 27.84 0.192 27.864 ;
    END
  END od[144]
  PIN od[145]
    DIRECTION OUTPUT ;
    USE SIGNAL ;
    PORT
      LAYER M4 ;
        RECT  0 28.032 0.192 28.056 ;
    END
  END od[145]
  PIN od[146]
    DIRECTION OUTPUT ;
    USE SIGNAL ;
    PORT
      LAYER M4 ;
        RECT  0 28.176 0.192 28.2 ;
    END
  END od[146]
  PIN od[147]
    DIRECTION OUTPUT ;
    USE SIGNAL ;
    PORT
      LAYER M4 ;
        RECT  0 28.32 0.192 28.344 ;
    END
  END od[147]
  PIN od[148]
    DIRECTION OUTPUT ;
    USE SIGNAL ;
    PORT
      LAYER M4 ;
        RECT  0 28.512 0.192 28.536 ;
    END
  END od[148]
  PIN od[149]
    DIRECTION OUTPUT ;
    USE SIGNAL ;
    PORT
      LAYER M4 ;
        RECT  0 28.656 0.192 28.68 ;
    END
  END od[149]
  PIN od[14]
    DIRECTION OUTPUT ;
    USE SIGNAL ;
    PORT
      LAYER M4 ;
        RECT  0 6.816 0.192 6.84 ;
    END
  END od[14]
  PIN od[150]
    DIRECTION OUTPUT ;
    USE SIGNAL ;
    PORT
      LAYER M4 ;
        RECT  0 28.8 0.192 28.824 ;
    END
  END od[150]
  PIN od[151]
    DIRECTION OUTPUT ;
    USE SIGNAL ;
    PORT
      LAYER M4 ;
        RECT  0 28.992 0.192 29.016 ;
    END
  END od[151]
  PIN od[152]
    DIRECTION OUTPUT ;
    USE SIGNAL ;
    PORT
      LAYER M4 ;
        RECT  0 29.136 0.192 29.16 ;
    END
  END od[152]
  PIN od[153]
    DIRECTION OUTPUT ;
    USE SIGNAL ;
    PORT
      LAYER M4 ;
        RECT  0 29.328 0.192 29.352 ;
    END
  END od[153]
  PIN od[154]
    DIRECTION OUTPUT ;
    USE SIGNAL ;
    PORT
      LAYER M4 ;
        RECT  0 29.472 0.192 29.496 ;
    END
  END od[154]
  PIN od[155]
    DIRECTION OUTPUT ;
    USE SIGNAL ;
    PORT
      LAYER M4 ;
        RECT  0 29.616 0.192 29.64 ;
    END
  END od[155]
  PIN od[156]
    DIRECTION OUTPUT ;
    USE SIGNAL ;
    PORT
      LAYER M4 ;
        RECT  0 29.808 0.192 29.832 ;
    END
  END od[156]
  PIN od[157]
    DIRECTION OUTPUT ;
    USE SIGNAL ;
    PORT
      LAYER M4 ;
        RECT  0 29.952 0.192 29.976 ;
    END
  END od[157]
  PIN od[158]
    DIRECTION OUTPUT ;
    USE SIGNAL ;
    PORT
      LAYER M4 ;
        RECT  0 30.096 0.192 30.12 ;
    END
  END od[158]
  PIN od[159]
    DIRECTION OUTPUT ;
    USE SIGNAL ;
    PORT
      LAYER M4 ;
        RECT  0 30.288 0.192 30.312 ;
    END
  END od[159]
  PIN od[15]
    DIRECTION OUTPUT ;
    USE SIGNAL ;
    PORT
      LAYER M4 ;
        RECT  0 7.008 0.192 7.032 ;
    END
  END od[15]
  PIN od[160]
    DIRECTION OUTPUT ;
    USE SIGNAL ;
    PORT
      LAYER M4 ;
        RECT  0 30.432 0.192 30.456 ;
    END
  END od[160]
  PIN od[161]
    DIRECTION OUTPUT ;
    USE SIGNAL ;
    PORT
      LAYER M4 ;
        RECT  0 30.576 0.192 30.6 ;
    END
  END od[161]
  PIN od[162]
    DIRECTION OUTPUT ;
    USE SIGNAL ;
    PORT
      LAYER M4 ;
        RECT  0 30.768 0.192 30.792 ;
    END
  END od[162]
  PIN od[163]
    DIRECTION OUTPUT ;
    USE SIGNAL ;
    PORT
      LAYER M4 ;
        RECT  0 30.912 0.192 30.936 ;
    END
  END od[163]
  PIN od[164]
    DIRECTION OUTPUT ;
    USE SIGNAL ;
    PORT
      LAYER M4 ;
        RECT  0 31.104 0.192 31.128 ;
    END
  END od[164]
  PIN od[165]
    DIRECTION OUTPUT ;
    USE SIGNAL ;
    PORT
      LAYER M4 ;
        RECT  0 31.248 0.192 31.272 ;
    END
  END od[165]
  PIN od[166]
    DIRECTION OUTPUT ;
    USE SIGNAL ;
    PORT
      LAYER M4 ;
        RECT  0 31.392 0.192 31.416 ;
    END
  END od[166]
  PIN od[167]
    DIRECTION OUTPUT ;
    USE SIGNAL ;
    PORT
      LAYER M4 ;
        RECT  0 31.584 0.192 31.608 ;
    END
  END od[167]
  PIN od[168]
    DIRECTION OUTPUT ;
    USE SIGNAL ;
    PORT
      LAYER M4 ;
        RECT  0 31.728 0.192 31.752 ;
    END
  END od[168]
  PIN od[169]
    DIRECTION OUTPUT ;
    USE SIGNAL ;
    PORT
      LAYER M4 ;
        RECT  0 31.872 0.192 31.896 ;
    END
  END od[169]
  PIN od[16]
    DIRECTION OUTPUT ;
    USE SIGNAL ;
    PORT
      LAYER M4 ;
        RECT  0 7.152 0.192 7.176 ;
    END
  END od[16]
  PIN od[170]
    DIRECTION OUTPUT ;
    USE SIGNAL ;
    PORT
      LAYER M4 ;
        RECT  0 32.064 0.192 32.088 ;
    END
  END od[170]
  PIN od[171]
    DIRECTION OUTPUT ;
    USE SIGNAL ;
    PORT
      LAYER M4 ;
        RECT  0 32.208 0.192 32.232 ;
    END
  END od[171]
  PIN od[172]
    DIRECTION OUTPUT ;
    USE SIGNAL ;
    PORT
      LAYER M4 ;
        RECT  0 32.352 0.192 32.376 ;
    END
  END od[172]
  PIN od[173]
    DIRECTION OUTPUT ;
    USE SIGNAL ;
    PORT
      LAYER M4 ;
        RECT  0 32.544 0.192 32.568 ;
    END
  END od[173]
  PIN od[174]
    DIRECTION OUTPUT ;
    USE SIGNAL ;
    PORT
      LAYER M4 ;
        RECT  0 32.688 0.192 32.712 ;
    END
  END od[174]
  PIN od[175]
    DIRECTION OUTPUT ;
    USE SIGNAL ;
    PORT
      LAYER M4 ;
        RECT  0 32.88 0.192 32.904 ;
    END
  END od[175]
  PIN od[176]
    DIRECTION OUTPUT ;
    USE SIGNAL ;
    PORT
      LAYER M4 ;
        RECT  0 33.024 0.192 33.048 ;
    END
  END od[176]
  PIN od[177]
    DIRECTION OUTPUT ;
    USE SIGNAL ;
    PORT
      LAYER M4 ;
        RECT  0 33.168 0.192 33.192 ;
    END
  END od[177]
  PIN od[178]
    DIRECTION OUTPUT ;
    USE SIGNAL ;
    PORT
      LAYER M4 ;
        RECT  0 33.36 0.192 33.384 ;
    END
  END od[178]
  PIN od[179]
    DIRECTION OUTPUT ;
    USE SIGNAL ;
    PORT
      LAYER M4 ;
        RECT  0 33.504 0.192 33.528 ;
    END
  END od[179]
  PIN od[17]
    DIRECTION OUTPUT ;
    USE SIGNAL ;
    PORT
      LAYER M4 ;
        RECT  0 7.344 0.192 7.368 ;
    END
  END od[17]
  PIN od[180]
    DIRECTION OUTPUT ;
    USE SIGNAL ;
    PORT
      LAYER M4 ;
        RECT  0 33.648 0.192 33.672 ;
    END
  END od[180]
  PIN od[181]
    DIRECTION OUTPUT ;
    USE SIGNAL ;
    PORT
      LAYER M4 ;
        RECT  0 33.84 0.192 33.864 ;
    END
  END od[181]
  PIN od[182]
    DIRECTION OUTPUT ;
    USE SIGNAL ;
    PORT
      LAYER M4 ;
        RECT  0 33.984 0.192 34.008 ;
    END
  END od[182]
  PIN od[183]
    DIRECTION OUTPUT ;
    USE SIGNAL ;
    PORT
      LAYER M4 ;
        RECT  0 34.176 0.192 34.2 ;
    END
  END od[183]
  PIN od[184]
    DIRECTION OUTPUT ;
    USE SIGNAL ;
    PORT
      LAYER M4 ;
        RECT  0 34.32 0.192 34.344 ;
    END
  END od[184]
  PIN od[185]
    DIRECTION OUTPUT ;
    USE SIGNAL ;
    PORT
      LAYER M4 ;
        RECT  0 34.464 0.192 34.488 ;
    END
  END od[185]
  PIN od[186]
    DIRECTION OUTPUT ;
    USE SIGNAL ;
    PORT
      LAYER M4 ;
        RECT  0 34.656 0.192 34.68 ;
    END
  END od[186]
  PIN od[187]
    DIRECTION OUTPUT ;
    USE SIGNAL ;
    PORT
      LAYER M4 ;
        RECT  0 34.8 0.192 34.824 ;
    END
  END od[187]
  PIN od[188]
    DIRECTION OUTPUT ;
    USE SIGNAL ;
    PORT
      LAYER M4 ;
        RECT  0 34.944 0.192 34.968 ;
    END
  END od[188]
  PIN od[189]
    DIRECTION OUTPUT ;
    USE SIGNAL ;
    PORT
      LAYER M4 ;
        RECT  0 35.136 0.192 35.16 ;
    END
  END od[189]
  PIN od[18]
    DIRECTION OUTPUT ;
    USE SIGNAL ;
    PORT
      LAYER M4 ;
        RECT  0 7.488 0.192 7.512 ;
    END
  END od[18]
  PIN od[190]
    DIRECTION OUTPUT ;
    USE SIGNAL ;
    PORT
      LAYER M4 ;
        RECT  0 35.28 0.192 35.304 ;
    END
  END od[190]
  PIN od[191]
    DIRECTION OUTPUT ;
    USE SIGNAL ;
    PORT
      LAYER M4 ;
        RECT  0 35.424 0.192 35.448 ;
    END
  END od[191]
  PIN od[192]
    DIRECTION OUTPUT ;
    USE SIGNAL ;
    PORT
      LAYER M4 ;
        RECT  0 35.616 0.192 35.64 ;
    END
  END od[192]
  PIN od[193]
    DIRECTION OUTPUT ;
    USE SIGNAL ;
    PORT
      LAYER M4 ;
        RECT  0 35.76 0.192 35.784 ;
    END
  END od[193]
  PIN od[194]
    DIRECTION OUTPUT ;
    USE SIGNAL ;
    PORT
      LAYER M4 ;
        RECT  0 35.952 0.192 35.976 ;
    END
  END od[194]
  PIN od[195]
    DIRECTION OUTPUT ;
    USE SIGNAL ;
    PORT
      LAYER M4 ;
        RECT  0 36.096 0.192 36.12 ;
    END
  END od[195]
  PIN od[196]
    DIRECTION OUTPUT ;
    USE SIGNAL ;
    PORT
      LAYER M4 ;
        RECT  0 36.24 0.192 36.264 ;
    END
  END od[196]
  PIN od[197]
    DIRECTION OUTPUT ;
    USE SIGNAL ;
    PORT
      LAYER M4 ;
        RECT  0 36.432 0.192 36.456 ;
    END
  END od[197]
  PIN od[198]
    DIRECTION OUTPUT ;
    USE SIGNAL ;
    PORT
      LAYER M4 ;
        RECT  0 36.576 0.192 36.6 ;
    END
  END od[198]
  PIN od[199]
    DIRECTION OUTPUT ;
    USE SIGNAL ;
    PORT
      LAYER M4 ;
        RECT  0 36.72 0.192 36.744 ;
    END
  END od[199]
  PIN od[19]
    DIRECTION OUTPUT ;
    USE SIGNAL ;
    PORT
      LAYER M4 ;
        RECT  0 7.632 0.192 7.656 ;
    END
  END od[19]
  PIN od[1]
    DIRECTION OUTPUT ;
    USE SIGNAL ;
    PORT
      LAYER M4 ;
        RECT  0 4.752 0.192 4.776 ;
    END
  END od[1]
  PIN od[200]
    DIRECTION OUTPUT ;
    USE SIGNAL ;
    PORT
      LAYER M4 ;
        RECT  0 36.912 0.192 36.936 ;
    END
  END od[200]
  PIN od[201]
    DIRECTION OUTPUT ;
    USE SIGNAL ;
    PORT
      LAYER M4 ;
        RECT  0 37.056 0.192 37.08 ;
    END
  END od[201]
  PIN od[202]
    DIRECTION OUTPUT ;
    USE SIGNAL ;
    PORT
      LAYER M4 ;
        RECT  0 37.248 0.192 37.272 ;
    END
  END od[202]
  PIN od[203]
    DIRECTION OUTPUT ;
    USE SIGNAL ;
    PORT
      LAYER M4 ;
        RECT  0 37.392 0.192 37.416 ;
    END
  END od[203]
  PIN od[204]
    DIRECTION OUTPUT ;
    USE SIGNAL ;
    PORT
      LAYER M4 ;
        RECT  0 37.536 0.192 37.56 ;
    END
  END od[204]
  PIN od[205]
    DIRECTION OUTPUT ;
    USE SIGNAL ;
    PORT
      LAYER M4 ;
        RECT  0 37.728 0.192 37.752 ;
    END
  END od[205]
  PIN od[206]
    DIRECTION OUTPUT ;
    USE SIGNAL ;
    PORT
      LAYER M4 ;
        RECT  0 37.872 0.192 37.896 ;
    END
  END od[206]
  PIN od[207]
    DIRECTION OUTPUT ;
    USE SIGNAL ;
    PORT
      LAYER M4 ;
        RECT  0 38.016 0.192 38.04 ;
    END
  END od[207]
  PIN od[208]
    DIRECTION OUTPUT ;
    USE SIGNAL ;
    PORT
      LAYER M4 ;
        RECT  0 38.208 0.192 38.232 ;
    END
  END od[208]
  PIN od[209]
    DIRECTION OUTPUT ;
    USE SIGNAL ;
    PORT
      LAYER M4 ;
        RECT  0 38.352 0.192 38.376 ;
    END
  END od[209]
  PIN od[20]
    DIRECTION OUTPUT ;
    USE SIGNAL ;
    PORT
      LAYER M4 ;
        RECT  0 7.824 0.192 7.848 ;
    END
  END od[20]
  PIN od[210]
    DIRECTION OUTPUT ;
    USE SIGNAL ;
    PORT
      LAYER M4 ;
        RECT  0 38.496 0.192 38.52 ;
    END
  END od[210]
  PIN od[211]
    DIRECTION OUTPUT ;
    USE SIGNAL ;
    PORT
      LAYER M4 ;
        RECT  0 38.688 0.192 38.712 ;
    END
  END od[211]
  PIN od[212]
    DIRECTION OUTPUT ;
    USE SIGNAL ;
    PORT
      LAYER M4 ;
        RECT  0 38.832 0.192 38.856 ;
    END
  END od[212]
  PIN od[213]
    DIRECTION OUTPUT ;
    USE SIGNAL ;
    PORT
      LAYER M4 ;
        RECT  0 39.024 0.192 39.048 ;
    END
  END od[213]
  PIN od[214]
    DIRECTION OUTPUT ;
    USE SIGNAL ;
    PORT
      LAYER M4 ;
        RECT  0 39.168 0.192 39.192 ;
    END
  END od[214]
  PIN od[215]
    DIRECTION OUTPUT ;
    USE SIGNAL ;
    PORT
      LAYER M4 ;
        RECT  0 39.312 0.192 39.336 ;
    END
  END od[215]
  PIN od[216]
    DIRECTION OUTPUT ;
    USE SIGNAL ;
    PORT
      LAYER M4 ;
        RECT  0 39.504 0.192 39.528 ;
    END
  END od[216]
  PIN od[217]
    DIRECTION OUTPUT ;
    USE SIGNAL ;
    PORT
      LAYER M4 ;
        RECT  0 39.648 0.192 39.672 ;
    END
  END od[217]
  PIN od[218]
    DIRECTION OUTPUT ;
    USE SIGNAL ;
    PORT
      LAYER M4 ;
        RECT  0 39.792 0.192 39.816 ;
    END
  END od[218]
  PIN od[219]
    DIRECTION OUTPUT ;
    USE SIGNAL ;
    PORT
      LAYER M4 ;
        RECT  0 39.984 0.192 40.008 ;
    END
  END od[219]
  PIN od[21]
    DIRECTION OUTPUT ;
    USE SIGNAL ;
    PORT
      LAYER M4 ;
        RECT  0 7.968 0.192 7.992 ;
    END
  END od[21]
  PIN od[220]
    DIRECTION OUTPUT ;
    USE SIGNAL ;
    PORT
      LAYER M4 ;
        RECT  0 40.128 0.192 40.152 ;
    END
  END od[220]
  PIN od[221]
    DIRECTION OUTPUT ;
    USE SIGNAL ;
    PORT
      LAYER M4 ;
        RECT  0 40.272 0.192 40.296 ;
    END
  END od[221]
  PIN od[222]
    DIRECTION OUTPUT ;
    USE SIGNAL ;
    PORT
      LAYER M4 ;
        RECT  0 40.464 0.192 40.488 ;
    END
  END od[222]
  PIN od[223]
    DIRECTION OUTPUT ;
    USE SIGNAL ;
    PORT
      LAYER M4 ;
        RECT  0 40.608 0.192 40.632 ;
    END
  END od[223]
  PIN od[224]
    DIRECTION OUTPUT ;
    USE SIGNAL ;
    PORT
      LAYER M4 ;
        RECT  0 40.8 0.192 40.824 ;
    END
  END od[224]
  PIN od[225]
    DIRECTION OUTPUT ;
    USE SIGNAL ;
    PORT
      LAYER M4 ;
        RECT  0 40.944 0.192 40.968 ;
    END
  END od[225]
  PIN od[226]
    DIRECTION OUTPUT ;
    USE SIGNAL ;
    PORT
      LAYER M4 ;
        RECT  0 41.088 0.192 41.112 ;
    END
  END od[226]
  PIN od[227]
    DIRECTION OUTPUT ;
    USE SIGNAL ;
    PORT
      LAYER M4 ;
        RECT  0 41.28 0.192 41.304 ;
    END
  END od[227]
  PIN od[228]
    DIRECTION OUTPUT ;
    USE SIGNAL ;
    PORT
      LAYER M4 ;
        RECT  0 41.424 0.192 41.448 ;
    END
  END od[228]
  PIN od[229]
    DIRECTION OUTPUT ;
    USE SIGNAL ;
    PORT
      LAYER M4 ;
        RECT  0 41.568 0.192 41.592 ;
    END
  END od[229]
  PIN od[22]
    DIRECTION OUTPUT ;
    USE SIGNAL ;
    PORT
      LAYER M4 ;
        RECT  0 8.112 0.192 8.136 ;
    END
  END od[22]
  PIN od[230]
    DIRECTION OUTPUT ;
    USE SIGNAL ;
    PORT
      LAYER M4 ;
        RECT  0 41.76 0.192 41.784 ;
    END
  END od[230]
  PIN od[231]
    DIRECTION OUTPUT ;
    USE SIGNAL ;
    PORT
      LAYER M4 ;
        RECT  0 41.904 0.192 41.928 ;
    END
  END od[231]
  PIN od[232]
    DIRECTION OUTPUT ;
    USE SIGNAL ;
    PORT
      LAYER M4 ;
        RECT  0 42.096 0.192 42.12 ;
    END
  END od[232]
  PIN od[233]
    DIRECTION OUTPUT ;
    USE SIGNAL ;
    PORT
      LAYER M4 ;
        RECT  0 42.24 0.192 42.264 ;
    END
  END od[233]
  PIN od[234]
    DIRECTION OUTPUT ;
    USE SIGNAL ;
    PORT
      LAYER M4 ;
        RECT  0 42.384 0.192 42.408 ;
    END
  END od[234]
  PIN od[235]
    DIRECTION OUTPUT ;
    USE SIGNAL ;
    PORT
      LAYER M4 ;
        RECT  0 42.576 0.192 42.6 ;
    END
  END od[235]
  PIN od[236]
    DIRECTION OUTPUT ;
    USE SIGNAL ;
    PORT
      LAYER M4 ;
        RECT  0 42.72 0.192 42.744 ;
    END
  END od[236]
  PIN od[237]
    DIRECTION OUTPUT ;
    USE SIGNAL ;
    PORT
      LAYER M4 ;
        RECT  0 42.864 0.192 42.888 ;
    END
  END od[237]
  PIN od[238]
    DIRECTION OUTPUT ;
    USE SIGNAL ;
    PORT
      LAYER M4 ;
        RECT  0 43.056 0.192 43.08 ;
    END
  END od[238]
  PIN od[239]
    DIRECTION OUTPUT ;
    USE SIGNAL ;
    PORT
      LAYER M4 ;
        RECT  0 43.2 0.192 43.224 ;
    END
  END od[239]
  PIN od[23]
    DIRECTION OUTPUT ;
    USE SIGNAL ;
    PORT
      LAYER M4 ;
        RECT  0 8.304 0.192 8.328 ;
    END
  END od[23]
  PIN od[240]
    DIRECTION OUTPUT ;
    USE SIGNAL ;
    PORT
      LAYER M4 ;
        RECT  0 43.344 0.192 43.368 ;
    END
  END od[240]
  PIN od[241]
    DIRECTION OUTPUT ;
    USE SIGNAL ;
    PORT
      LAYER M4 ;
        RECT  0 43.536 0.192 43.56 ;
    END
  END od[241]
  PIN od[242]
    DIRECTION OUTPUT ;
    USE SIGNAL ;
    PORT
      LAYER M4 ;
        RECT  0 43.68 0.192 43.704 ;
    END
  END od[242]
  PIN od[243]
    DIRECTION OUTPUT ;
    USE SIGNAL ;
    PORT
      LAYER M4 ;
        RECT  0 43.872 0.192 43.896 ;
    END
  END od[243]
  PIN od[244]
    DIRECTION OUTPUT ;
    USE SIGNAL ;
    PORT
      LAYER M4 ;
        RECT  0 44.016 0.192 44.04 ;
    END
  END od[244]
  PIN od[245]
    DIRECTION OUTPUT ;
    USE SIGNAL ;
    PORT
      LAYER M4 ;
        RECT  0 44.16 0.192 44.184 ;
    END
  END od[245]
  PIN od[246]
    DIRECTION OUTPUT ;
    USE SIGNAL ;
    PORT
      LAYER M4 ;
        RECT  0 44.352 0.192 44.376 ;
    END
  END od[246]
  PIN od[247]
    DIRECTION OUTPUT ;
    USE SIGNAL ;
    PORT
      LAYER M4 ;
        RECT  0 44.496 0.192 44.52 ;
    END
  END od[247]
  PIN od[248]
    DIRECTION OUTPUT ;
    USE SIGNAL ;
    PORT
      LAYER M4 ;
        RECT  0 44.64 0.192 44.664 ;
    END
  END od[248]
  PIN od[249]
    DIRECTION OUTPUT ;
    USE SIGNAL ;
    PORT
      LAYER M4 ;
        RECT  0 44.832 0.192 44.856 ;
    END
  END od[249]
  PIN od[24]
    DIRECTION OUTPUT ;
    USE SIGNAL ;
    PORT
      LAYER M4 ;
        RECT  0 8.448 0.192 8.472 ;
    END
  END od[24]
  PIN od[250]
    DIRECTION OUTPUT ;
    USE SIGNAL ;
    PORT
      LAYER M4 ;
        RECT  0 44.976 0.192 45 ;
    END
  END od[250]
  PIN od[251]
    DIRECTION OUTPUT ;
    USE SIGNAL ;
    PORT
      LAYER M4 ;
        RECT  0 45.168 0.192 45.192 ;
    END
  END od[251]
  PIN od[252]
    DIRECTION OUTPUT ;
    USE SIGNAL ;
    PORT
      LAYER M4 ;
        RECT  0 45.312 0.192 45.336 ;
    END
  END od[252]
  PIN od[253]
    DIRECTION OUTPUT ;
    USE SIGNAL ;
    PORT
      LAYER M4 ;
        RECT  0 45.456 0.192 45.48 ;
    END
  END od[253]
  PIN od[254]
    DIRECTION OUTPUT ;
    USE SIGNAL ;
    PORT
      LAYER M4 ;
        RECT  0 45.648 0.192 45.672 ;
    END
  END od[254]
  PIN od[255]
    DIRECTION OUTPUT ;
    USE SIGNAL ;
    PORT
      LAYER M4 ;
        RECT  0 45.792 0.192 45.816 ;
    END
  END od[255]
  PIN od[256]
    DIRECTION OUTPUT ;
    USE SIGNAL ;
    PORT
      LAYER M4 ;
        RECT  0 45.936 0.192 45.96 ;
    END
  END od[256]
  PIN od[257]
    DIRECTION OUTPUT ;
    USE SIGNAL ;
    PORT
      LAYER M4 ;
        RECT  0 46.128 0.192 46.152 ;
    END
  END od[257]
  PIN od[258]
    DIRECTION OUTPUT ;
    USE SIGNAL ;
    PORT
      LAYER M4 ;
        RECT  0 46.272 0.192 46.296 ;
    END
  END od[258]
  PIN od[259]
    DIRECTION OUTPUT ;
    USE SIGNAL ;
    PORT
      LAYER M4 ;
        RECT  0 46.416 0.192 46.44 ;
    END
  END od[259]
  PIN od[25]
    DIRECTION OUTPUT ;
    USE SIGNAL ;
    PORT
      LAYER M4 ;
        RECT  0 8.592 0.192 8.616 ;
    END
  END od[25]
  PIN od[260]
    DIRECTION OUTPUT ;
    USE SIGNAL ;
    PORT
      LAYER M4 ;
        RECT  0 46.608 0.192 46.632 ;
    END
  END od[260]
  PIN od[261]
    DIRECTION OUTPUT ;
    USE SIGNAL ;
    PORT
      LAYER M4 ;
        RECT  0 46.752 0.192 46.776 ;
    END
  END od[261]
  PIN od[262]
    DIRECTION OUTPUT ;
    USE SIGNAL ;
    PORT
      LAYER M4 ;
        RECT  0 46.944 0.192 46.968 ;
    END
  END od[262]
  PIN od[263]
    DIRECTION OUTPUT ;
    USE SIGNAL ;
    PORT
      LAYER M4 ;
        RECT  0 47.088 0.192 47.112 ;
    END
  END od[263]
  PIN od[264]
    DIRECTION OUTPUT ;
    USE SIGNAL ;
    PORT
      LAYER M4 ;
        RECT  0 47.232 0.192 47.256 ;
    END
  END od[264]
  PIN od[265]
    DIRECTION OUTPUT ;
    USE SIGNAL ;
    PORT
      LAYER M4 ;
        RECT  0 47.424 0.192 47.448 ;
    END
  END od[265]
  PIN od[266]
    DIRECTION OUTPUT ;
    USE SIGNAL ;
    PORT
      LAYER M4 ;
        RECT  0 47.568 0.192 47.592 ;
    END
  END od[266]
  PIN od[267]
    DIRECTION OUTPUT ;
    USE SIGNAL ;
    PORT
      LAYER M4 ;
        RECT  0 47.712 0.192 47.736 ;
    END
  END od[267]
  PIN od[268]
    DIRECTION OUTPUT ;
    USE SIGNAL ;
    PORT
      LAYER M4 ;
        RECT  0 47.904 0.192 47.928 ;
    END
  END od[268]
  PIN od[269]
    DIRECTION OUTPUT ;
    USE SIGNAL ;
    PORT
      LAYER M4 ;
        RECT  0 48.048 0.192 48.072 ;
    END
  END od[269]
  PIN od[26]
    DIRECTION OUTPUT ;
    USE SIGNAL ;
    PORT
      LAYER M4 ;
        RECT  0 8.784 0.192 8.808 ;
    END
  END od[26]
  PIN od[270]
    DIRECTION OUTPUT ;
    USE SIGNAL ;
    PORT
      LAYER M4 ;
        RECT  0 48.192 0.192 48.216 ;
    END
  END od[270]
  PIN od[271]
    DIRECTION OUTPUT ;
    USE SIGNAL ;
    PORT
      LAYER M4 ;
        RECT  0 48.384 0.192 48.408 ;
    END
  END od[271]
  PIN od[272]
    DIRECTION OUTPUT ;
    USE SIGNAL ;
    PORT
      LAYER M4 ;
        RECT  0 48.528 0.192 48.552 ;
    END
  END od[272]
  PIN od[273]
    DIRECTION OUTPUT ;
    USE SIGNAL ;
    PORT
      LAYER M4 ;
        RECT  0 48.72 0.192 48.744 ;
    END
  END od[273]
  PIN od[274]
    DIRECTION OUTPUT ;
    USE SIGNAL ;
    PORT
      LAYER M4 ;
        RECT  0 48.864 0.192 48.888 ;
    END
  END od[274]
  PIN od[275]
    DIRECTION OUTPUT ;
    USE SIGNAL ;
    PORT
      LAYER M4 ;
        RECT  0 49.008 0.192 49.032 ;
    END
  END od[275]
  PIN od[276]
    DIRECTION OUTPUT ;
    USE SIGNAL ;
    PORT
      LAYER M4 ;
        RECT  0 49.2 0.192 49.224 ;
    END
  END od[276]
  PIN od[277]
    DIRECTION OUTPUT ;
    USE SIGNAL ;
    PORT
      LAYER M4 ;
        RECT  0 49.344 0.192 49.368 ;
    END
  END od[277]
  PIN od[278]
    DIRECTION OUTPUT ;
    USE SIGNAL ;
    PORT
      LAYER M4 ;
        RECT  0 49.488 0.192 49.512 ;
    END
  END od[278]
  PIN od[279]
    DIRECTION OUTPUT ;
    USE SIGNAL ;
    PORT
      LAYER M4 ;
        RECT  0 49.68 0.192 49.704 ;
    END
  END od[279]
  PIN od[27]
    DIRECTION OUTPUT ;
    USE SIGNAL ;
    PORT
      LAYER M4 ;
        RECT  0 8.928 0.192 8.952 ;
    END
  END od[27]
  PIN od[280]
    DIRECTION OUTPUT ;
    USE SIGNAL ;
    PORT
      LAYER M4 ;
        RECT  0 49.824 0.192 49.848 ;
    END
  END od[280]
  PIN od[281]
    DIRECTION OUTPUT ;
    USE SIGNAL ;
    PORT
      LAYER M4 ;
        RECT  0 50.016 0.192 50.04 ;
    END
  END od[281]
  PIN od[282]
    DIRECTION OUTPUT ;
    USE SIGNAL ;
    PORT
      LAYER M4 ;
        RECT  0 50.16 0.192 50.184 ;
    END
  END od[282]
  PIN od[283]
    DIRECTION OUTPUT ;
    USE SIGNAL ;
    PORT
      LAYER M4 ;
        RECT  0 50.304 0.192 50.328 ;
    END
  END od[283]
  PIN od[284]
    DIRECTION OUTPUT ;
    USE SIGNAL ;
    PORT
      LAYER M4 ;
        RECT  0 50.496 0.192 50.52 ;
    END
  END od[284]
  PIN od[285]
    DIRECTION OUTPUT ;
    USE SIGNAL ;
    PORT
      LAYER M4 ;
        RECT  0 50.64 0.192 50.664 ;
    END
  END od[285]
  PIN od[286]
    DIRECTION OUTPUT ;
    USE SIGNAL ;
    PORT
      LAYER M4 ;
        RECT  0 50.784 0.192 50.808 ;
    END
  END od[286]
  PIN od[287]
    DIRECTION OUTPUT ;
    USE SIGNAL ;
    PORT
      LAYER M4 ;
        RECT  0 50.976 0.192 51 ;
    END
  END od[287]
  PIN od[288]
    DIRECTION OUTPUT ;
    USE SIGNAL ;
    PORT
      LAYER M4 ;
        RECT  0 51.12 0.192 51.144 ;
    END
  END od[288]
  PIN od[289]
    DIRECTION OUTPUT ;
    USE SIGNAL ;
    PORT
      LAYER M4 ;
        RECT  0 51.264 0.192 51.288 ;
    END
  END od[289]
  PIN od[28]
    DIRECTION OUTPUT ;
    USE SIGNAL ;
    PORT
      LAYER M4 ;
        RECT  0 9.12 0.192 9.144 ;
    END
  END od[28]
  PIN od[290]
    DIRECTION OUTPUT ;
    USE SIGNAL ;
    PORT
      LAYER M4 ;
        RECT  0 51.456 0.192 51.48 ;
    END
  END od[290]
  PIN od[291]
    DIRECTION OUTPUT ;
    USE SIGNAL ;
    PORT
      LAYER M4 ;
        RECT  0 51.6 0.192 51.624 ;
    END
  END od[291]
  PIN od[292]
    DIRECTION OUTPUT ;
    USE SIGNAL ;
    PORT
      LAYER M4 ;
        RECT  0 51.792 0.192 51.816 ;
    END
  END od[292]
  PIN od[29]
    DIRECTION OUTPUT ;
    USE SIGNAL ;
    PORT
      LAYER M4 ;
        RECT  0 9.264 0.192 9.288 ;
    END
  END od[29]
  PIN od[2]
    DIRECTION OUTPUT ;
    USE SIGNAL ;
    PORT
      LAYER M4 ;
        RECT  0 4.896 0.192 4.92 ;
    END
  END od[2]
  PIN od[30]
    DIRECTION OUTPUT ;
    USE SIGNAL ;
    PORT
      LAYER M4 ;
        RECT  0 9.408 0.192 9.432 ;
    END
  END od[30]
  PIN od[31]
    DIRECTION OUTPUT ;
    USE SIGNAL ;
    PORT
      LAYER M4 ;
        RECT  0 9.6 0.192 9.624 ;
    END
  END od[31]
  PIN od[32]
    DIRECTION OUTPUT ;
    USE SIGNAL ;
    PORT
      LAYER M4 ;
        RECT  0 9.744 0.192 9.768 ;
    END
  END od[32]
  PIN od[33]
    DIRECTION OUTPUT ;
    USE SIGNAL ;
    PORT
      LAYER M4 ;
        RECT  0 9.888 0.192 9.912 ;
    END
  END od[33]
  PIN od[34]
    DIRECTION OUTPUT ;
    USE SIGNAL ;
    PORT
      LAYER M4 ;
        RECT  0 10.08 0.192 10.104 ;
    END
  END od[34]
  PIN od[35]
    DIRECTION OUTPUT ;
    USE SIGNAL ;
    PORT
      LAYER M4 ;
        RECT  0 10.224 0.192 10.248 ;
    END
  END od[35]
  PIN od[36]
    DIRECTION OUTPUT ;
    USE SIGNAL ;
    PORT
      LAYER M4 ;
        RECT  0 10.416 0.192 10.44 ;
    END
  END od[36]
  PIN od[37]
    DIRECTION OUTPUT ;
    USE SIGNAL ;
    PORT
      LAYER M4 ;
        RECT  0 10.56 0.192 10.584 ;
    END
  END od[37]
  PIN od[38]
    DIRECTION OUTPUT ;
    USE SIGNAL ;
    PORT
      LAYER M4 ;
        RECT  0 10.704 0.192 10.728 ;
    END
  END od[38]
  PIN od[39]
    DIRECTION OUTPUT ;
    USE SIGNAL ;
    PORT
      LAYER M4 ;
        RECT  0 10.896 0.192 10.92 ;
    END
  END od[39]
  PIN od[3]
    DIRECTION OUTPUT ;
    USE SIGNAL ;
    PORT
      LAYER M4 ;
        RECT  0 5.04 0.192 5.064 ;
    END
  END od[3]
  PIN od[40]
    DIRECTION OUTPUT ;
    USE SIGNAL ;
    PORT
      LAYER M4 ;
        RECT  0 11.04 0.192 11.064 ;
    END
  END od[40]
  PIN od[41]
    DIRECTION OUTPUT ;
    USE SIGNAL ;
    PORT
      LAYER M4 ;
        RECT  0 11.184 0.192 11.208 ;
    END
  END od[41]
  PIN od[42]
    DIRECTION OUTPUT ;
    USE SIGNAL ;
    PORT
      LAYER M4 ;
        RECT  0 11.376 0.192 11.4 ;
    END
  END od[42]
  PIN od[43]
    DIRECTION OUTPUT ;
    USE SIGNAL ;
    PORT
      LAYER M4 ;
        RECT  0 11.52 0.192 11.544 ;
    END
  END od[43]
  PIN od[44]
    DIRECTION OUTPUT ;
    USE SIGNAL ;
    PORT
      LAYER M4 ;
        RECT  0 11.664 0.192 11.688 ;
    END
  END od[44]
  PIN od[45]
    DIRECTION OUTPUT ;
    USE SIGNAL ;
    PORT
      LAYER M4 ;
        RECT  0 11.856 0.192 11.88 ;
    END
  END od[45]
  PIN od[46]
    DIRECTION OUTPUT ;
    USE SIGNAL ;
    PORT
      LAYER M4 ;
        RECT  0 12 0.192 12.024 ;
    END
  END od[46]
  PIN od[47]
    DIRECTION OUTPUT ;
    USE SIGNAL ;
    PORT
      LAYER M4 ;
        RECT  0 12.192 0.192 12.216 ;
    END
  END od[47]
  PIN od[48]
    DIRECTION OUTPUT ;
    USE SIGNAL ;
    PORT
      LAYER M4 ;
        RECT  0 12.336 0.192 12.36 ;
    END
  END od[48]
  PIN od[49]
    DIRECTION OUTPUT ;
    USE SIGNAL ;
    PORT
      LAYER M4 ;
        RECT  0 12.48 0.192 12.504 ;
    END
  END od[49]
  PIN od[4]
    DIRECTION OUTPUT ;
    USE SIGNAL ;
    PORT
      LAYER M4 ;
        RECT  0 5.232 0.192 5.256 ;
    END
  END od[4]
  PIN od[50]
    DIRECTION OUTPUT ;
    USE SIGNAL ;
    PORT
      LAYER M4 ;
        RECT  0 12.672 0.192 12.696 ;
    END
  END od[50]
  PIN od[51]
    DIRECTION OUTPUT ;
    USE SIGNAL ;
    PORT
      LAYER M4 ;
        RECT  0 12.816 0.192 12.84 ;
    END
  END od[51]
  PIN od[52]
    DIRECTION OUTPUT ;
    USE SIGNAL ;
    PORT
      LAYER M4 ;
        RECT  0 12.96 0.192 12.984 ;
    END
  END od[52]
  PIN od[53]
    DIRECTION OUTPUT ;
    USE SIGNAL ;
    PORT
      LAYER M4 ;
        RECT  0 13.152 0.192 13.176 ;
    END
  END od[53]
  PIN od[54]
    DIRECTION OUTPUT ;
    USE SIGNAL ;
    PORT
      LAYER M4 ;
        RECT  0 13.296 0.192 13.32 ;
    END
  END od[54]
  PIN od[55]
    DIRECTION OUTPUT ;
    USE SIGNAL ;
    PORT
      LAYER M4 ;
        RECT  0 13.488 0.192 13.512 ;
    END
  END od[55]
  PIN od[56]
    DIRECTION OUTPUT ;
    USE SIGNAL ;
    PORT
      LAYER M4 ;
        RECT  0 13.632 0.192 13.656 ;
    END
  END od[56]
  PIN od[57]
    DIRECTION OUTPUT ;
    USE SIGNAL ;
    PORT
      LAYER M4 ;
        RECT  0 13.776 0.192 13.8 ;
    END
  END od[57]
  PIN od[58]
    DIRECTION OUTPUT ;
    USE SIGNAL ;
    PORT
      LAYER M4 ;
        RECT  0 13.968 0.192 13.992 ;
    END
  END od[58]
  PIN od[59]
    DIRECTION OUTPUT ;
    USE SIGNAL ;
    PORT
      LAYER M4 ;
        RECT  0 14.112 0.192 14.136 ;
    END
  END od[59]
  PIN od[5]
    DIRECTION OUTPUT ;
    USE SIGNAL ;
    PORT
      LAYER M4 ;
        RECT  0 5.376 0.192 5.4 ;
    END
  END od[5]
  PIN od[60]
    DIRECTION OUTPUT ;
    USE SIGNAL ;
    PORT
      LAYER M4 ;
        RECT  0 14.256 0.192 14.28 ;
    END
  END od[60]
  PIN od[61]
    DIRECTION OUTPUT ;
    USE SIGNAL ;
    PORT
      LAYER M4 ;
        RECT  0 14.448 0.192 14.472 ;
    END
  END od[61]
  PIN od[62]
    DIRECTION OUTPUT ;
    USE SIGNAL ;
    PORT
      LAYER M4 ;
        RECT  0 14.592 0.192 14.616 ;
    END
  END od[62]
  PIN od[63]
    DIRECTION OUTPUT ;
    USE SIGNAL ;
    PORT
      LAYER M4 ;
        RECT  0 14.736 0.192 14.76 ;
    END
  END od[63]
  PIN od[64]
    DIRECTION OUTPUT ;
    USE SIGNAL ;
    PORT
      LAYER M4 ;
        RECT  0 14.928 0.192 14.952 ;
    END
  END od[64]
  PIN od[65]
    DIRECTION OUTPUT ;
    USE SIGNAL ;
    PORT
      LAYER M4 ;
        RECT  0 15.072 0.192 15.096 ;
    END
  END od[65]
  PIN od[66]
    DIRECTION OUTPUT ;
    USE SIGNAL ;
    PORT
      LAYER M4 ;
        RECT  0 15.264 0.192 15.288 ;
    END
  END od[66]
  PIN od[67]
    DIRECTION OUTPUT ;
    USE SIGNAL ;
    PORT
      LAYER M4 ;
        RECT  0 15.408 0.192 15.432 ;
    END
  END od[67]
  PIN od[68]
    DIRECTION OUTPUT ;
    USE SIGNAL ;
    PORT
      LAYER M4 ;
        RECT  0 15.552 0.192 15.576 ;
    END
  END od[68]
  PIN od[69]
    DIRECTION OUTPUT ;
    USE SIGNAL ;
    PORT
      LAYER M4 ;
        RECT  0 15.744 0.192 15.768 ;
    END
  END od[69]
  PIN od[6]
    DIRECTION OUTPUT ;
    USE SIGNAL ;
    PORT
      LAYER M4 ;
        RECT  0 5.568 0.192 5.592 ;
    END
  END od[6]
  PIN od[70]
    DIRECTION OUTPUT ;
    USE SIGNAL ;
    PORT
      LAYER M4 ;
        RECT  0 15.888 0.192 15.912 ;
    END
  END od[70]
  PIN od[71]
    DIRECTION OUTPUT ;
    USE SIGNAL ;
    PORT
      LAYER M4 ;
        RECT  0 16.032 0.192 16.056 ;
    END
  END od[71]
  PIN od[72]
    DIRECTION OUTPUT ;
    USE SIGNAL ;
    PORT
      LAYER M4 ;
        RECT  0 16.224 0.192 16.248 ;
    END
  END od[72]
  PIN od[73]
    DIRECTION OUTPUT ;
    USE SIGNAL ;
    PORT
      LAYER M4 ;
        RECT  0 16.368 0.192 16.392 ;
    END
  END od[73]
  PIN od[74]
    DIRECTION OUTPUT ;
    USE SIGNAL ;
    PORT
      LAYER M4 ;
        RECT  0 16.512 0.192 16.536 ;
    END
  END od[74]
  PIN od[75]
    DIRECTION OUTPUT ;
    USE SIGNAL ;
    PORT
      LAYER M4 ;
        RECT  0 16.704 0.192 16.728 ;
    END
  END od[75]
  PIN od[76]
    DIRECTION OUTPUT ;
    USE SIGNAL ;
    PORT
      LAYER M4 ;
        RECT  0 16.848 0.192 16.872 ;
    END
  END od[76]
  PIN od[77]
    DIRECTION OUTPUT ;
    USE SIGNAL ;
    PORT
      LAYER M4 ;
        RECT  0 17.04 0.192 17.064 ;
    END
  END od[77]
  PIN od[78]
    DIRECTION OUTPUT ;
    USE SIGNAL ;
    PORT
      LAYER M4 ;
        RECT  0 17.184 0.192 17.208 ;
    END
  END od[78]
  PIN od[79]
    DIRECTION OUTPUT ;
    USE SIGNAL ;
    PORT
      LAYER M4 ;
        RECT  0 17.328 0.192 17.352 ;
    END
  END od[79]
  PIN od[7]
    DIRECTION OUTPUT ;
    USE SIGNAL ;
    PORT
      LAYER M4 ;
        RECT  0 5.712 0.192 5.736 ;
    END
  END od[7]
  PIN od[80]
    DIRECTION OUTPUT ;
    USE SIGNAL ;
    PORT
      LAYER M4 ;
        RECT  0 17.52 0.192 17.544 ;
    END
  END od[80]
  PIN od[81]
    DIRECTION OUTPUT ;
    USE SIGNAL ;
    PORT
      LAYER M4 ;
        RECT  0 17.664 0.192 17.688 ;
    END
  END od[81]
  PIN od[82]
    DIRECTION OUTPUT ;
    USE SIGNAL ;
    PORT
      LAYER M4 ;
        RECT  0 17.808 0.192 17.832 ;
    END
  END od[82]
  PIN od[83]
    DIRECTION OUTPUT ;
    USE SIGNAL ;
    PORT
      LAYER M4 ;
        RECT  0 18 0.192 18.024 ;
    END
  END od[83]
  PIN od[84]
    DIRECTION OUTPUT ;
    USE SIGNAL ;
    PORT
      LAYER M4 ;
        RECT  0 18.144 0.192 18.168 ;
    END
  END od[84]
  PIN od[85]
    DIRECTION OUTPUT ;
    USE SIGNAL ;
    PORT
      LAYER M4 ;
        RECT  0 18.336 0.192 18.36 ;
    END
  END od[85]
  PIN od[86]
    DIRECTION OUTPUT ;
    USE SIGNAL ;
    PORT
      LAYER M4 ;
        RECT  0 18.48 0.192 18.504 ;
    END
  END od[86]
  PIN od[87]
    DIRECTION OUTPUT ;
    USE SIGNAL ;
    PORT
      LAYER M4 ;
        RECT  0 18.624 0.192 18.648 ;
    END
  END od[87]
  PIN od[88]
    DIRECTION OUTPUT ;
    USE SIGNAL ;
    PORT
      LAYER M4 ;
        RECT  0 18.816 0.192 18.84 ;
    END
  END od[88]
  PIN od[89]
    DIRECTION OUTPUT ;
    USE SIGNAL ;
    PORT
      LAYER M4 ;
        RECT  0 18.96 0.192 18.984 ;
    END
  END od[89]
  PIN od[8]
    DIRECTION OUTPUT ;
    USE SIGNAL ;
    PORT
      LAYER M4 ;
        RECT  0 5.856 0.192 5.88 ;
    END
  END od[8]
  PIN od[90]
    DIRECTION OUTPUT ;
    USE SIGNAL ;
    PORT
      LAYER M4 ;
        RECT  0 19.104 0.192 19.128 ;
    END
  END od[90]
  PIN od[91]
    DIRECTION OUTPUT ;
    USE SIGNAL ;
    PORT
      LAYER M4 ;
        RECT  0 19.296 0.192 19.32 ;
    END
  END od[91]
  PIN od[92]
    DIRECTION OUTPUT ;
    USE SIGNAL ;
    PORT
      LAYER M4 ;
        RECT  0 19.44 0.192 19.464 ;
    END
  END od[92]
  PIN od[93]
    DIRECTION OUTPUT ;
    USE SIGNAL ;
    PORT
      LAYER M4 ;
        RECT  0 19.584 0.192 19.608 ;
    END
  END od[93]
  PIN od[94]
    DIRECTION OUTPUT ;
    USE SIGNAL ;
    PORT
      LAYER M4 ;
        RECT  0 19.776 0.192 19.8 ;
    END
  END od[94]
  PIN od[95]
    DIRECTION OUTPUT ;
    USE SIGNAL ;
    PORT
      LAYER M4 ;
        RECT  0 19.92 0.192 19.944 ;
    END
  END od[95]
  PIN od[96]
    DIRECTION OUTPUT ;
    USE SIGNAL ;
    PORT
      LAYER M4 ;
        RECT  0 20.112 0.192 20.136 ;
    END
  END od[96]
  PIN od[97]
    DIRECTION OUTPUT ;
    USE SIGNAL ;
    PORT
      LAYER M4 ;
        RECT  0 20.256 0.192 20.28 ;
    END
  END od[97]
  PIN od[98]
    DIRECTION OUTPUT ;
    USE SIGNAL ;
    PORT
      LAYER M4 ;
        RECT  0 20.4 0.192 20.424 ;
    END
  END od[98]
  PIN od[99]
    DIRECTION OUTPUT ;
    USE SIGNAL ;
    PORT
      LAYER M4 ;
        RECT  0 20.592 0.192 20.616 ;
    END
  END od[99]
  PIN od[9]
    DIRECTION OUTPUT ;
    USE SIGNAL ;
    PORT
      LAYER M4 ;
        RECT  0 6.048 0.192 6.072 ;
    END
  END od[9]
  PIN rs[0]
    DIRECTION INPUT ;
    USE SIGNAL ;
    PORT
      LAYER M3 ;
        RECT  27.252 0 27.27 0.144 ;
    END
    PORT
      LAYER M3 ;
        RECT  27.252 0.108 27.27 2.143 ;
    END
  END rs[0]
  PIN rss[0]
    DIRECTION INPUT ;
    USE SIGNAL ;
    PORT
      LAYER M5 ;
        RECT  36.432 0 36.456 0.192 ;
    END
    PORT
      LAYER M5 ;
        RECT  36.432 0.144 36.456 1.763 ;
    END
  END rss[0]
  PIN st[0]
    DIRECTION OUTPUT ;
    USE SIGNAL ;
    PORT
      LAYER M3 ;
        RECT  40.716 56.016 40.734 56.16 ;
    END
  END st[0]
  PIN st[1]
    DIRECTION OUTPUT ;
    USE SIGNAL ;
    PORT
      LAYER M5 ;
        RECT  40.848 55.968 40.872 56.16 ;
    END
  END st[1]
  PIN st[2]
    DIRECTION OUTPUT ;
    USE SIGNAL ;
    PORT
      LAYER M3 ;
        RECT  40.968 56.016 40.986 56.16 ;
    END
  END st[2]
  PIN VDD
    DIRECTION INOUT ;
    USE POWER ;
    PORT
      LAYER M5 ;
        RECT  43.092 2.151 43.212 54.009 ;
        RECT  40.392 2.151 40.512 54.009 ;
        RECT  37.692 2.151 37.812 54.009 ;
        RECT  34.992 2.151 35.112 54.009 ;
        RECT  32.292 2.151 32.412 54.009 ;
        RECT  29.592 2.151 29.712 54.009 ;
        RECT  26.892 2.151 27.012 54.009 ;
        RECT  24.192 2.151 24.312 54.009 ;
        RECT  21.492 2.151 21.612 54.009 ;
        RECT  18.792 2.151 18.912 54.009 ;
        RECT  16.092 2.151 16.212 54.009 ;
        RECT  13.392 2.151 13.512 54.009 ;
        RECT  10.692 2.151 10.812 54.009 ;
        RECT  7.992 2.151 8.112 54.009 ;
        RECT  5.292 2.151 5.412 54.009 ;
        RECT  2.592 2.151 2.712 54.009 ;
    END
  END VDD
  PIN VSS
    DIRECTION INOUT ;
    USE GROUND ;
    PORT
      LAYER M5 ;
        RECT  42.9 2.137 43.02 54.023 ;
        RECT  40.2 2.137 40.32 54.023 ;
        RECT  37.5 2.137 37.62 54.023 ;
        RECT  34.8 2.137 34.92 54.023 ;
        RECT  32.1 2.137 32.22 54.023 ;
        RECT  29.4 2.137 29.52 54.023 ;
        RECT  26.7 2.137 26.82 54.023 ;
        RECT  24 2.137 24.12 54.023 ;
        RECT  21.3 2.137 21.42 54.023 ;
        RECT  18.6 2.137 18.72 54.023 ;
        RECT  15.9 2.137 16.02 54.023 ;
        RECT  13.2 2.137 13.32 54.023 ;
        RECT  10.5 2.137 10.62 54.023 ;
        RECT  7.8 2.137 7.92 54.023 ;
        RECT  5.1 2.137 5.22 54.023 ;
        RECT  2.4 2.137 2.52 54.023 ;
    END
  END VSS
  # OT_OBS_CLOSED layer=M5 d_um=1.536 added=37
  OBS
    LAYER RVTN ;
     RECT  2.16 2.16 43.2 2.295 ;
     RECT  2.16 2.565 43.2 2.835 ;
     RECT  2.16 3.105 43.2 3.375 ;
     RECT  2.16 3.645 43.2 3.915 ;
     RECT  2.16 4.185 43.2 4.455 ;
     RECT  2.16 4.725 43.2 4.995 ;
     RECT  2.16 5.265 43.2 5.535 ;
     RECT  2.16 5.805 43.2 6.075 ;
     RECT  2.16 6.345 43.2 6.615 ;
     RECT  2.16 6.885 43.2 7.155 ;
     RECT  2.16 7.425 43.2 7.695 ;
     RECT  2.16 7.965 43.2 8.235 ;
     RECT  2.16 8.505 43.2 8.775 ;
     RECT  2.16 9.045 43.2 9.315 ;
     RECT  2.16 9.585 43.2 9.855 ;
     RECT  2.16 10.125 43.2 10.395 ;
     RECT  2.16 10.665 43.2 10.935 ;
     RECT  2.16 11.205 43.2 11.475 ;
     RECT  2.16 11.745 43.2 12.015 ;
     RECT  2.16 12.285 43.2 12.555 ;
     RECT  2.16 12.825 43.2 13.095 ;
     RECT  2.16 13.365 43.2 13.635 ;
     RECT  2.16 13.905 43.2 14.175 ;
     RECT  2.16 14.445 43.2 14.715 ;
     RECT  2.16 14.985 43.2 15.255 ;
     RECT  2.16 15.525 43.2 15.795 ;
     RECT  2.16 16.065 43.2 16.335 ;
     RECT  2.16 16.605 43.2 16.875 ;
     RECT  2.16 17.145 43.2 17.415 ;
     RECT  2.16 17.685 43.2 17.955 ;
     RECT  2.16 18.225 43.2 18.495 ;
     RECT  2.16 18.765 43.2 19.035 ;
     RECT  2.16 19.305 43.2 19.575 ;
     RECT  2.16 19.845 43.2 20.115 ;
     RECT  2.16 20.385 43.2 20.655 ;
     RECT  2.16 20.925 43.2 21.195 ;
     RECT  2.16 21.465 43.2 21.735 ;
     RECT  2.16 22.005 43.2 22.275 ;
     RECT  2.16 22.545 43.2 22.815 ;
     RECT  2.16 23.085 43.2 23.355 ;
     RECT  2.16 23.625 43.2 23.895 ;
     RECT  2.16 24.165 43.2 24.435 ;
     RECT  2.16 24.705 43.2 24.975 ;
     RECT  2.16 25.245 43.2 25.515 ;
     RECT  2.16 25.785 43.2 26.055 ;
     RECT  2.16 26.325 43.2 26.595 ;
     RECT  2.16 26.865 43.2 27.135 ;
     RECT  2.16 27.405 43.2 27.675 ;
     RECT  2.16 27.945 43.2 28.215 ;
     RECT  2.16 28.485 43.2 28.755 ;
     RECT  2.16 29.025 43.2 29.295 ;
     RECT  2.16 29.565 43.2 29.835 ;
     RECT  2.16 30.105 43.2 30.375 ;
     RECT  2.16 30.645 43.2 30.915 ;
     RECT  2.16 31.185 43.2 31.455 ;
     RECT  2.16 31.725 43.2 31.995 ;
     RECT  2.16 32.265 43.2 32.535 ;
     RECT  2.16 32.805 43.2 33.075 ;
     RECT  2.16 33.345 43.2 33.615 ;
     RECT  2.16 33.885 43.2 34.155 ;
     RECT  2.16 34.425 43.2 34.695 ;
     RECT  2.16 34.965 43.2 35.235 ;
     RECT  2.16 35.505 43.2 35.775 ;
     RECT  2.16 36.045 43.2 36.315 ;
     RECT  2.16 36.585 43.2 36.855 ;
     RECT  2.16 37.125 43.2 37.395 ;
     RECT  2.16 37.665 43.2 37.935 ;
     RECT  2.16 38.205 43.2 38.475 ;
     RECT  2.16 38.745 43.2 39.015 ;
     RECT  2.16 39.285 43.2 39.555 ;
     RECT  2.16 39.825 43.2 40.095 ;
     RECT  2.16 40.365 43.2 40.635 ;
     RECT  2.16 40.905 43.2 41.175 ;
     RECT  2.16 41.445 43.2 41.715 ;
     RECT  2.16 41.985 43.2 42.255 ;
     RECT  2.16 42.525 43.2 42.795 ;
     RECT  2.16 43.065 43.2 43.335 ;
     RECT  2.16 43.605 43.2 43.875 ;
     RECT  2.16 44.145 43.2 44.415 ;
     RECT  2.16 44.685 43.2 44.955 ;
     RECT  2.16 45.225 43.2 45.495 ;
     RECT  2.16 45.765 43.2 46.035 ;
     RECT  2.16 46.305 43.2 46.575 ;
     RECT  2.16 46.845 43.2 47.115 ;
     RECT  2.16 47.385 43.2 47.655 ;
     RECT  2.16 47.925 43.2 48.195 ;
     RECT  2.16 48.465 43.2 48.735 ;
     RECT  2.16 49.005 43.2 49.275 ;
     RECT  2.16 49.545 43.2 49.815 ;
     RECT  2.16 50.085 43.2 50.355 ;
     RECT  2.16 50.625 43.2 50.895 ;
     RECT  2.16 51.165 43.2 51.435 ;
     RECT  2.16 51.705 43.2 51.975 ;
     RECT  2.16 52.245 43.2 52.515 ;
     RECT  2.16 52.785 43.2 53.055 ;
     RECT  2.16 53.325 43.2 53.595 ;
     RECT  2.16 53.865 43.2 54 ;
    LAYER RVTP ;
     RECT  2.16 2.295 43.2 2.565 ;
     RECT  2.16 2.835 43.2 3.105 ;
     RECT  2.16 3.375 43.2 3.645 ;
     RECT  2.16 3.915 43.2 4.185 ;
     RECT  2.16 4.455 43.2 4.725 ;
     RECT  2.16 4.995 43.2 5.265 ;
     RECT  2.16 5.535 43.2 5.805 ;
     RECT  2.16 6.075 43.2 6.345 ;
     RECT  2.16 6.615 43.2 6.885 ;
     RECT  2.16 7.155 43.2 7.425 ;
     RECT  2.16 7.695 43.2 7.965 ;
     RECT  2.16 8.235 43.2 8.505 ;
     RECT  2.16 8.775 43.2 9.045 ;
     RECT  2.16 9.315 43.2 9.585 ;
     RECT  2.16 9.855 43.2 10.125 ;
     RECT  2.16 10.395 43.2 10.665 ;
     RECT  2.16 10.935 43.2 11.205 ;
     RECT  2.16 11.475 43.2 11.745 ;
     RECT  2.16 12.015 43.2 12.285 ;
     RECT  2.16 12.555 43.2 12.825 ;
     RECT  2.16 13.095 43.2 13.365 ;
     RECT  2.16 13.635 43.2 13.905 ;
     RECT  2.16 14.175 43.2 14.445 ;
     RECT  2.16 14.715 43.2 14.985 ;
     RECT  2.16 15.255 43.2 15.525 ;
     RECT  2.16 15.795 43.2 16.065 ;
     RECT  2.16 16.335 43.2 16.605 ;
     RECT  2.16 16.875 43.2 17.145 ;
     RECT  2.16 17.415 43.2 17.685 ;
     RECT  2.16 17.955 43.2 18.225 ;
     RECT  2.16 18.495 43.2 18.765 ;
     RECT  2.16 19.035 43.2 19.305 ;
     RECT  2.16 19.575 43.2 19.845 ;
     RECT  2.16 20.115 43.2 20.385 ;
     RECT  2.16 20.655 43.2 20.925 ;
     RECT  2.16 21.195 43.2 21.465 ;
     RECT  2.16 21.735 43.2 22.005 ;
     RECT  2.16 22.275 43.2 22.545 ;
     RECT  2.16 22.815 43.2 23.085 ;
     RECT  2.16 23.355 43.2 23.625 ;
     RECT  2.16 23.895 43.2 24.165 ;
     RECT  2.16 24.435 43.2 24.705 ;
     RECT  2.16 24.975 43.2 25.245 ;
     RECT  2.16 25.515 43.2 25.785 ;
     RECT  2.16 26.055 43.2 26.325 ;
     RECT  2.16 26.595 43.2 26.865 ;
     RECT  2.16 27.135 43.2 27.405 ;
     RECT  2.16 27.675 43.2 27.945 ;
     RECT  2.16 28.215 43.2 28.485 ;
     RECT  2.16 28.755 43.2 29.025 ;
     RECT  2.16 29.295 43.2 29.565 ;
     RECT  2.16 29.835 43.2 30.105 ;
     RECT  2.16 30.375 43.2 30.645 ;
     RECT  2.16 30.915 43.2 31.185 ;
     RECT  2.16 31.455 43.2 31.725 ;
     RECT  2.16 31.995 43.2 32.265 ;
     RECT  2.16 32.535 43.2 32.805 ;
     RECT  2.16 33.075 43.2 33.345 ;
     RECT  2.16 33.615 43.2 33.885 ;
     RECT  2.16 34.155 43.2 34.425 ;
     RECT  2.16 34.695 43.2 34.965 ;
     RECT  2.16 35.235 43.2 35.505 ;
     RECT  2.16 35.775 43.2 36.045 ;
     RECT  2.16 36.315 43.2 36.585 ;
     RECT  2.16 36.855 43.2 37.125 ;
     RECT  2.16 37.395 43.2 37.665 ;
     RECT  2.16 37.935 43.2 38.205 ;
     RECT  2.16 38.475 43.2 38.745 ;
     RECT  2.16 39.015 43.2 39.285 ;
     RECT  2.16 39.555 43.2 39.825 ;
     RECT  2.16 40.095 43.2 40.365 ;
     RECT  2.16 40.635 43.2 40.905 ;
     RECT  2.16 41.175 43.2 41.445 ;
     RECT  2.16 41.715 43.2 41.985 ;
     RECT  2.16 42.255 43.2 42.525 ;
     RECT  2.16 42.795 43.2 43.065 ;
     RECT  2.16 43.335 43.2 43.605 ;
     RECT  2.16 43.875 43.2 44.145 ;
     RECT  2.16 44.415 43.2 44.685 ;
     RECT  2.16 44.955 43.2 45.225 ;
     RECT  2.16 45.495 43.2 45.765 ;
     RECT  2.16 46.035 43.2 46.305 ;
     RECT  2.16 46.575 43.2 46.845 ;
     RECT  2.16 47.115 43.2 47.385 ;
     RECT  2.16 47.655 43.2 47.925 ;
     RECT  2.16 48.195 43.2 48.465 ;
     RECT  2.16 48.735 43.2 49.005 ;
     RECT  2.16 49.275 43.2 49.545 ;
     RECT  2.16 49.815 43.2 50.085 ;
     RECT  2.16 50.355 43.2 50.625 ;
     RECT  2.16 50.895 43.2 51.165 ;
     RECT  2.16 51.435 43.2 51.705 ;
     RECT  2.16 51.975 43.2 52.245 ;
     RECT  2.16 52.515 43.2 52.785 ;
     RECT  2.16 53.055 43.2 53.325 ;
     RECT  2.16 53.595 43.2 53.865 ;
    LAYER M1 ;
     RECT  2.16 2.151 43.2 54.009 ;
    LAYER M2 ;
     RECT  0.211 44.496 0.283 44.514 ;
     RECT  0.283 44.388 0.311 44.514 ;
     RECT  0.311 44.388 0.383 44.406 ;
     RECT  0.211 50.706 0.535 50.724 ;
     RECT  0.211 6.246 2.16 6.264 ;
     RECT  2.083 15.606 2.16 15.624 ;
     RECT  0.535 17.496 2.16 17.514 ;
     RECT  0.211 18.666 2.16 18.684 ;
     RECT  0.535 21.636 2.16 21.654 ;
     RECT  0.211 27.306 2.16 27.324 ;
     RECT  0.535 28.188 2.16 28.206 ;
     RECT  0.211 33.516 2.16 33.534 ;
     RECT  0.535 36.756 2.16 36.774 ;
     RECT  2.155 38.178 2.16 38.196 ;
     RECT  0.535 41.994 2.16 42.012 ;
     RECT  0.211 47.826 2.16 47.844 ;
     RECT  0.535 50.436 2.16 50.724 ;
     RECT  2.16 2.151 5.035 54.009 ;
     RECT  5.035 2.151 5.135 54.09 ;
     RECT  8.815 0.531 8.915 0.549 ;
     RECT  5.135 2.151 10.471 54.009 ;
     RECT  10.471 2.151 10.607 54.09 ;
     RECT  10.607 2.151 13.171 54.009 ;
     RECT  13.171 2.151 13.343 54.09 ;
     RECT  13.343 2.151 21.235 54.009 ;
     RECT  21.235 2.151 21.335 54.09 ;
     RECT  21.335 2.151 24.043 54.009 ;
     RECT  24.043 2.151 24.179 54.09 ;
     RECT  24.179 2.151 26.779 54.009 ;
     RECT  26.779 2.151 26.879 54.09 ;
     RECT  26.879 2.151 29.371 54.009 ;
     RECT  29.371 2.151 29.543 54.09 ;
     RECT  29.543 2.151 39.703 54.009 ;
     RECT  39.703 2.151 40.559 54.738 ;
     RECT  40.559 2.151 43.2 54.009 ;
     RECT  43.2 2.421 43.212 53.739 ;
    LAYER M3 ;
     RECT  8.82 0.52 8.91 0.554 ;
     RECT  8.82 0.554 8.838 0.557 ;
     RECT  36.36 1.723 36.378 2.263 ;
     RECT  36.36 2.263 36.486 2.335 ;
     RECT  36.144 2.335 36.486 2.371 ;
     RECT  2.415 2.143 2.505 2.413 ;
     RECT  5.115 2.143 5.205 2.413 ;
     RECT  7.815 2.143 7.905 2.413 ;
     RECT  10.515 2.143 10.605 2.413 ;
     RECT  13.215 2.143 13.305 2.413 ;
     RECT  15.915 2.143 16.005 2.413 ;
     RECT  18.615 2.143 18.705 2.413 ;
     RECT  21.315 2.143 21.405 2.413 ;
     RECT  24.015 2.143 24.105 2.413 ;
     RECT  29.415 2.143 29.505 2.413 ;
     RECT  32.115 2.143 32.205 2.413 ;
     RECT  34.815 2.143 34.905 2.413 ;
     RECT  37.515 2.143 37.605 2.413 ;
     RECT  40.215 2.143 40.305 2.413 ;
     RECT  42.915 2.143 43.005 2.413 ;
     RECT  36.144 2.371 36.558 2.605 ;
     RECT  37.515 2.413 37.797 2.605 ;
     RECT  34.815 2.413 35.097 2.911 ;
     RECT  36.144 2.605 37.797 2.911 ;
     RECT  34.815 2.911 37.797 3.407 ;
     RECT  36.576 3.407 37.797 3.443 ;
     RECT  34.815 3.407 35.802 3.485 ;
     RECT  37.044 3.443 37.797 3.569 ;
     RECT  2.415 2.413 2.697 4.555 ;
     RECT  2.304 4.555 2.697 4.747 ;
     RECT  5.115 2.413 5.397 4.765 ;
     RECT  37.116 3.569 37.797 4.829 ;
     RECT  7.815 2.413 8.097 4.891 ;
     RECT  2.304 4.747 2.754 4.987 ;
     RECT  0.252 4.891 0.27 5.021 ;
     RECT  2.304 4.987 3.366 5.161 ;
     RECT  4.5 4.765 5.397 5.161 ;
     RECT  2.304 5.161 5.397 5.269 ;
     RECT  7.815 4.891 8.406 5.305 ;
     RECT  2.304 5.269 5.454 5.333 ;
     RECT  4.5 5.333 5.454 5.467 ;
     RECT  2.304 5.333 3.33 5.549 ;
     RECT  4.5 5.467 5.706 5.611 ;
     RECT  7.308 5.305 8.406 5.611 ;
     RECT  4.5 5.611 8.406 6.139 ;
     RECT  0.216 6.241 0.234 6.365 ;
     RECT  4.356 6.139 8.406 6.385 ;
     RECT  2.304 5.549 3.222 6.619 ;
     RECT  4.032 6.385 8.406 6.619 ;
     RECT  2.304 6.619 8.406 7.889 ;
     RECT  2.304 7.889 2.934 8.107 ;
     RECT  2.268 8.107 2.934 8.159 ;
     RECT  12.276 8.155 12.294 8.477 ;
     RECT  3.924 7.889 8.406 8.699 ;
     RECT  2.304 8.159 2.934 8.941 ;
     RECT  2.304 8.941 3.042 9.085 ;
     RECT  4.248 8.699 8.406 9.239 ;
     RECT  2.304 9.085 3.438 9.481 ;
     RECT  2.304 9.481 3.69 9.779 ;
     RECT  4.464 9.239 8.406 9.823 ;
     RECT  4.464 9.823 8.766 10.093 ;
     RECT  2.304 9.779 3.186 10.123 ;
     RECT  2.016 10.123 3.186 10.253 ;
     RECT  3.996 10.093 8.766 10.561 ;
     RECT  2.304 10.253 3.186 10.66 ;
     RECT  3.996 10.561 9.486 10.705 ;
     RECT  3.96 10.705 9.486 10.939 ;
     RECT  10.515 2.413 10.797 10.975 ;
     RECT  2.304 10.66 3.222 11.011 ;
     RECT  3.96 10.939 9.522 11.011 ;
     RECT  2.304 11.011 9.702 11.399 ;
     RECT  4.032 11.399 9.702 11.408 ;
     RECT  4.428 11.408 9.702 11.911 ;
     RECT  10.515 10.975 10.998 11.911 ;
     RECT  4.428 11.911 10.998 12.181 ;
     RECT  2.304 11.399 3.15 12.475 ;
     RECT  2.304 12.475 3.258 12.631 ;
     RECT  2.304 12.631 3.402 12.793 ;
     RECT  4.14 12.181 10.998 12.793 ;
     RECT  2.304 12.793 10.998 12.893 ;
     RECT  3.996 12.893 10.998 13.559 ;
     RECT  0.252 13.483 0.27 13.613 ;
     RECT  2.304 12.893 3.078 13.639 ;
     RECT  2.304 13.639 3.474 13.661 ;
     RECT  2.412 13.661 3.474 13.829 ;
     RECT  4.464 13.559 10.998 13.909 ;
     RECT  11.952 13.675 11.97 13.909 ;
     RECT  0.216 13.867 0.234 13.997 ;
     RECT  4.464 13.909 11.97 14.347 ;
     RECT  2.412 13.829 2.862 14.443 ;
     RECT  4.356 14.347 11.97 14.449 ;
     RECT  2.304 14.443 2.862 14.587 ;
     RECT  2.268 14.587 2.862 14.611 ;
     RECT  2.268 14.611 2.934 14.731 ;
     RECT  2.268 14.731 3.366 14.755 ;
     RECT  4.356 14.449 12.474 14.755 ;
     RECT  2.268 14.755 12.474 14.989 ;
     RECT  13.215 2.413 13.497 14.989 ;
     RECT  2.268 14.989 13.497 15.179 ;
     RECT  2.268 15.179 2.934 15.251 ;
     RECT  2.268 15.251 2.898 15.403 ;
     RECT  2.088 15.403 2.898 15.629 ;
     RECT  3.744 15.179 13.497 15.961 ;
     RECT  2.304 15.629 2.898 16.105 ;
     RECT  3.672 15.961 13.497 16.105 ;
     RECT  2.304 16.105 13.497 16.109 ;
     RECT  2.304 16.109 3.69 16.133 ;
     RECT  2.304 16.133 3.546 16.529 ;
     RECT  2.304 16.529 3.294 16.541 ;
     RECT  4.5 16.109 13.497 16.807 ;
     RECT  4.5 16.807 13.626 16.879 ;
     RECT  4.032 16.879 13.626 17.041 ;
     RECT  4.032 17.041 13.734 17.311 ;
     RECT  0.216 17.323 0.234 17.453 ;
     RECT  4.032 17.311 14.382 17.491 ;
     RECT  0.54 17.491 0.558 17.693 ;
     RECT  3.492 17.491 14.382 17.761 ;
     RECT  2.304 16.541 2.697 17.887 ;
     RECT  3.492 17.761 14.778 17.887 ;
     RECT  15.915 2.413 16.197 18.301 ;
     RECT  2.304 17.887 14.778 18.653 ;
     RECT  0.216 18.661 0.234 18.845 ;
     RECT  2.415 18.653 14.778 18.959 ;
     RECT  4.464 18.959 14.778 18.967 ;
     RECT  15.516 18.301 16.197 18.967 ;
     RECT  2.415 18.959 3.618 19.381 ;
     RECT  2.304 19.381 3.618 19.469 ;
     RECT  4.464 18.967 16.197 19.615 ;
     RECT  2.412 19.469 3.618 19.921 ;
     RECT  4.464 19.615 16.65 19.921 ;
     RECT  0.252 19.819 0.27 19.949 ;
     RECT  2.412 19.921 16.65 19.949 ;
     RECT  2.412 19.949 2.898 20.039 ;
     RECT  3.816 19.949 16.65 20.111 ;
     RECT  2.412 20.039 2.754 20.251 ;
     RECT  3.996 20.111 16.65 20.461 ;
     RECT  2.304 20.251 2.754 20.489 ;
     RECT  3.996 20.461 16.794 20.587 ;
     RECT  2.412 20.489 2.754 20.821 ;
     RECT  2.412 20.821 2.826 21.001 ;
     RECT  3.996 20.587 17.19 21.001 ;
     RECT  0.216 20.971 0.234 21.101 ;
     RECT  2.412 21.001 17.19 21.127 ;
     RECT  2.412 21.127 17.838 21.271 ;
     RECT  2.376 21.271 17.838 21.361 ;
     RECT  18.615 2.413 18.897 21.361 ;
     RECT  0.252 21.451 0.27 21.581 ;
     RECT  0.54 21.631 0.558 21.725 ;
     RECT  2.304 21.361 17.838 21.811 ;
     RECT  2.268 21.811 17.838 21.929 ;
     RECT  4.212 21.929 17.838 22.081 ;
     RECT  18.615 21.361 19.026 22.081 ;
     RECT  2.268 21.929 3.438 22.271 ;
     RECT  4.212 22.081 19.026 22.739 ;
     RECT  4.248 22.739 19.026 22.811 ;
     RECT  2.304 22.271 3.438 22.981 ;
     RECT  2.304 22.981 3.474 23.153 ;
     RECT  2.304 23.153 3.294 23.179 ;
     RECT  4.536 22.811 19.026 23.323 ;
     RECT  19.8 22.711 19.818 23.323 ;
     RECT  2.232 23.179 3.294 23.351 ;
     RECT  2.304 23.351 3.294 23.585 ;
     RECT  4.536 23.323 19.818 23.659 ;
     RECT  21.315 2.413 21.597 24.331 ;
     RECT  2.304 23.585 3.006 24.427 ;
     RECT  2.304 24.427 3.078 24.475 ;
     RECT  4.032 23.659 19.818 24.475 ;
     RECT  2.304 24.475 19.818 24.509 ;
     RECT  4.608 24.509 19.818 24.601 ;
     RECT  4.608 24.601 19.998 24.871 ;
     RECT  20.916 24.331 21.597 24.871 ;
     RECT  2.304 24.509 3.87 24.989 ;
     RECT  3.42 24.989 3.87 25.169 ;
     RECT  26.715 2.143 27.27 25.321 ;
     RECT  2.304 24.989 2.697 25.469 ;
     RECT  4.608 24.871 21.597 25.555 ;
     RECT  2.415 25.469 2.697 25.723 ;
     RECT  3.42 25.169 3.582 25.723 ;
     RECT  2.415 25.723 3.582 26.221 ;
     RECT  25.956 26.257 25.974 26.293 ;
     RECT  26.715 25.321 27.342 26.293 ;
     RECT  2.304 26.221 3.582 26.347 ;
     RECT  4.428 25.555 21.597 26.347 ;
     RECT  25.128 26.329 25.146 26.401 ;
     RECT  25.956 26.293 27.342 26.401 ;
     RECT  0.252 25.915 0.27 26.429 ;
     RECT  1.26 26.299 1.278 26.539 ;
     RECT  25.128 26.401 27.342 26.555 ;
     RECT  1.152 26.539 1.278 26.573 ;
     RECT  25.92 26.555 27.342 26.627 ;
     RECT  1.152 26.573 1.17 26.669 ;
     RECT  25.128 26.555 25.146 26.789 ;
     RECT  25.92 26.627 27.198 26.789 ;
     RECT  2.304 26.347 21.597 26.905 ;
     RECT  2.304 26.905 21.654 27.139 ;
     RECT  2.304 27.139 21.906 27.329 ;
     RECT  26.28 26.789 27.198 27.365 ;
     RECT  0.216 27.301 0.234 27.389 ;
     RECT  4.608 27.329 21.906 27.679 ;
     RECT  23.04 27.337 23.058 27.679 ;
     RECT  4.608 27.679 23.058 27.913 ;
     RECT  24.015 2.413 24.297 27.913 ;
     RECT  2.304 27.329 3.834 28.171 ;
     RECT  4.608 27.913 23.13 28.171 ;
     RECT  24.015 27.913 24.426 28.183 ;
     RECT  2.304 28.171 23.13 28.291 ;
     RECT  24.015 28.183 24.534 28.291 ;
     RECT  2.304 28.291 24.534 28.481 ;
     RECT  0.54 28.183 0.558 28.541 ;
     RECT  26.715 27.365 27.198 28.687 ;
     RECT  4.212 28.481 24.534 29.021 ;
     RECT  4.284 29.021 24.534 29.029 ;
     RECT  2.304 28.481 3.366 29.093 ;
     RECT  4.284 29.029 25.146 29.399 ;
     RECT  41.652 4.801 41.67 29.461 ;
     RECT  26.715 28.687 27.342 29.489 ;
     RECT  4.356 29.399 25.146 29.605 ;
     RECT  2.304 29.093 3.294 29.831 ;
     RECT  4.356 29.605 25.506 30.181 ;
     RECT  26.715 29.489 26.997 30.181 ;
     RECT  3.996 30.181 26.997 30.605 ;
     RECT  2.304 29.831 2.934 30.685 ;
     RECT  2.304 30.685 3.15 30.811 ;
     RECT  0.252 30.763 0.27 30.893 ;
     RECT  3.996 30.605 4.05 30.947 ;
     RECT  2.304 30.811 3.258 30.991 ;
     RECT  4.968 30.605 26.997 31.081 ;
     RECT  2.304 30.991 3.51 31.181 ;
     RECT  4.968 31.081 27.666 31.351 ;
     RECT  2.304 31.181 3.438 31.415 ;
     RECT  4.248 31.351 27.666 32.161 ;
     RECT  3.996 32.161 27.666 32.237 ;
     RECT  2.304 31.415 2.934 32.341 ;
     RECT  2.304 32.341 3.906 32.908 ;
     RECT  2.268 32.908 3.906 32.999 ;
     RECT  1.26 32.875 1.278 33.053 ;
     RECT  2.304 32.999 3.906 33.067 ;
     RECT  4.716 32.237 27.666 33.067 ;
     RECT  0.216 33.511 0.234 33.677 ;
     RECT  29.415 2.413 29.697 34.897 ;
     RECT  2.304 33.067 27.666 35.501 ;
     RECT  3.744 35.501 27.666 35.609 ;
     RECT  3.996 35.609 27.666 35.707 ;
     RECT  28.728 34.897 29.697 35.707 ;
     RECT  2.304 35.501 2.862 36.331 ;
     RECT  0.216 36.331 0.234 36.461 ;
     RECT  2.304 36.331 2.97 36.481 ;
     RECT  3.996 35.707 29.697 36.481 ;
     RECT  0.54 36.751 0.558 37.085 ;
     RECT  2.304 36.481 29.697 37.327 ;
     RECT  2.304 37.327 29.826 38.011 ;
     RECT  2.16 38.011 29.826 38.201 ;
     RECT  32.115 2.413 32.397 39.181 ;
     RECT  2.304 38.201 29.826 39.451 ;
     RECT  31.032 38.479 31.05 39.451 ;
     RECT  2.304 39.451 31.05 40.091 ;
     RECT  3.816 40.091 31.05 40.289 ;
     RECT  2.304 40.091 2.898 40.459 ;
     RECT  2.268 40.459 2.898 40.631 ;
     RECT  2.304 40.631 2.898 40.837 ;
     RECT  2.304 40.837 3.294 40.877 ;
     RECT  4.248 40.289 31.05 41.143 ;
     RECT  3.78 41.143 31.194 41.243 ;
     RECT  0.216 41.179 0.234 41.309 ;
     RECT  2.304 40.877 2.862 41.755 ;
     RECT  2.304 41.755 3.114 41.909 ;
     RECT  31.968 39.181 32.397 41.953 ;
     RECT  3.996 41.243 31.194 41.989 ;
     RECT  3.888 41.989 31.194 42.179 ;
     RECT  0.54 41.989 0.558 42.413 ;
     RECT  2.304 41.909 2.754 42.727 ;
     RECT  31.968 41.953 32.598 43.141 ;
     RECT  0.252 43.099 0.27 43.229 ;
     RECT  33.444 42.061 33.462 43.231 ;
     RECT  31.932 43.141 32.598 43.267 ;
     RECT  3.96 42.179 31.194 43.303 ;
     RECT  2.304 42.727 2.934 43.339 ;
     RECT  3.744 43.303 31.194 43.339 ;
     RECT  31.932 43.267 32.706 43.771 ;
     RECT  33.444 43.231 33.786 43.771 ;
     RECT  0.288 44.347 0.306 44.383 ;
     RECT  0.288 44.383 0.378 44.429 ;
     RECT  0.288 44.429 0.306 44.491 ;
     RECT  0.216 44.491 0.306 44.519 ;
     RECT  0.216 44.519 0.234 44.528 ;
     RECT  31.932 43.771 33.786 44.617 ;
     RECT  2.304 43.339 31.194 44.645 ;
     RECT  34.815 3.485 35.097 44.689 ;
     RECT  3.6 44.645 31.194 44.923 ;
     RECT  31.932 44.617 33.93 44.923 ;
     RECT  3.6 44.923 33.93 44.951 ;
     RECT  34.815 44.689 35.226 44.959 ;
     RECT  2.304 44.645 2.862 45.149 ;
     RECT  3.96 44.951 33.93 45.419 ;
     RECT  4.032 45.419 33.93 45.455 ;
     RECT  34.74 44.959 35.226 45.931 ;
     RECT  36.288 45.121 36.306 45.931 ;
     RECT  4.968 45.455 33.93 46.003 ;
     RECT  34.74 45.931 36.306 46.003 ;
     RECT  4.032 45.455 4.05 46.219 ;
     RECT  4.968 46.003 36.306 46.219 ;
     RECT  37.515 4.829 37.797 46.471 ;
     RECT  0.216 46.411 0.234 46.541 ;
     RECT  4.032 46.219 36.306 46.541 ;
     RECT  2.304 45.149 2.754 46.579 ;
     RECT  2.304 46.579 3.114 46.741 ;
     RECT  2.304 46.741 3.69 47.111 ;
     RECT  4.536 46.541 36.306 47.317 ;
     RECT  37.476 46.471 37.797 47.425 ;
     RECT  3.996 47.317 36.306 47.551 ;
     RECT  37.296 47.425 37.797 47.551 ;
     RECT  2.304 47.111 3.222 47.849 ;
     RECT  2.304 47.849 2.754 47.885 ;
     RECT  0.216 47.821 0.234 47.933 ;
     RECT  3.996 47.551 37.797 48.091 ;
     RECT  3.996 48.091 37.854 48.119 ;
     RECT  4.14 48.119 37.854 48.163 ;
     RECT  4.14 48.163 38.034 48.271 ;
     RECT  4.14 48.271 38.358 48.469 ;
     RECT  40.215 2.413 40.497 48.505 ;
     RECT  2.304 47.885 2.697 48.715 ;
     RECT  4.14 48.469 38.682 48.937 ;
     RECT  4.14 48.937 38.79 48.973 ;
     RECT  40.176 48.505 40.497 49.009 ;
     RECT  3.996 48.973 38.79 49.081 ;
     RECT  2.304 48.715 2.97 49.379 ;
     RECT  2.412 49.379 2.97 49.585 ;
     RECT  3.96 49.081 38.79 49.585 ;
     RECT  0.216 49.579 0.234 49.709 ;
     RECT  2.412 49.585 38.79 49.783 ;
     RECT  39.564 49.009 40.497 49.783 ;
     RECT  2.412 49.783 40.497 49.855 ;
     RECT  41.652 29.461 42.174 49.855 ;
     RECT  2.412 49.855 42.174 50.125 ;
     RECT  42.915 2.413 43.197 50.125 ;
     RECT  2.412 50.125 43.197 50.155 ;
     RECT  0.54 50.431 0.558 50.701 ;
     RECT  0.216 50.701 0.558 50.813 ;
     RECT  0.252 50.813 0.558 51.005 ;
     RECT  2.304 50.155 43.197 51.437 ;
     RECT  4.14 51.437 43.197 51.533 ;
     RECT  0.252 51.005 0.27 51.629 ;
     RECT  4.212 51.533 43.197 51.629 ;
     RECT  4.464 51.629 43.197 51.665 ;
     RECT  2.304 51.437 3.294 51.899 ;
     RECT  2.415 51.899 3.294 51.935 ;
     RECT  4.608 51.665 43.197 52.411 ;
     RECT  4.248 52.411 43.197 52.447 ;
     RECT  3.996 52.447 43.197 52.709 ;
     RECT  4.14 52.709 43.197 53.563 ;
     RECT  2.415 51.935 2.697 53.747 ;
     RECT  4.068 53.563 43.197 53.747 ;
     RECT  4.068 53.747 43.005 53.789 ;
     RECT  4.356 53.789 43.005 53.861 ;
     RECT  41.976 53.861 43.005 53.933 ;
     RECT  41.976 53.933 42.174 53.969 ;
     RECT  2.415 53.747 2.505 54.017 ;
     RECT  42.915 53.933 43.005 54.017 ;
     RECT  42.156 53.969 42.174 54.125 ;
     RECT  4.356 53.861 40.986 56.028 ;
    LAYER M4 ;
     RECT  0.156 4.416 2.408 51.816 ;
     RECT  2.408 2.148 2.512 54.012 ;
     RECT  2.512 2.418 2.704 53.742 ;
     RECT  2.704 9.6 2.729 37.416 ;
     RECT  2.729 26.016 2.765 37.416 ;
     RECT  2.704 38.496 2.765 51.528 ;
     RECT  2.704 4.512 2.819 8.328 ;
     RECT  2.729 9.6 2.837 24.984 ;
     RECT  2.765 26.016 2.837 32.232 ;
     RECT  2.765 33.36 2.837 36.648 ;
     RECT  2.765 38.496 2.837 45.192 ;
     RECT  2.837 26.016 2.873 29.64 ;
     RECT  2.837 9.6 2.909 24.456 ;
     RECT  2.837 30.912 2.945 32.232 ;
     RECT  2.765 46.512 2.981 51.528 ;
     RECT  2.837 38.496 3.125 39.336 ;
     RECT  2.909 20.592 3.299 24.456 ;
     RECT  2.909 9.6 3.305 14.76 ;
     RECT  2.909 16.032 3.305 19.32 ;
     RECT  3.299 22.176 3.34 24.456 ;
     RECT  2.819 4.992 3.377 8.328 ;
     RECT  3.305 10.128 3.377 14.76 ;
     RECT  2.837 33.552 3.377 36.648 ;
     RECT  3.125 38.736 3.377 39.336 ;
     RECT  3.377 36.096 3.557 36.648 ;
     RECT  2.945 32.208 3.769 32.232 ;
     RECT  3.305 16.032 3.845 19.128 ;
     RECT  3.845 16.08 3.917 19.128 ;
     RECT  2.945 30.912 3.973 30.936 ;
     RECT  3.769 32.208 3.973 32.472 ;
     RECT  3.377 33.552 3.973 33.576 ;
     RECT  3.377 5.472 3.985 8.328 ;
     RECT  3.34 23.664 4.021 24.456 ;
     RECT  3.377 10.128 4.025 14.376 ;
     RECT  3.299 20.592 4.025 21 ;
     RECT  3.973 30.912 4.025 33.576 ;
     RECT  3.557 36.096 4.025 36.12 ;
     RECT  4.025 10.128 4.061 12.216 ;
     RECT  4.021 23.664 4.061 24.504 ;
     RECT  2.873 26.064 4.061 29.64 ;
     RECT  4.025 30.912 4.061 31.896 ;
     RECT  2.837 40.848 4.097 45.192 ;
     RECT  4.025 13.44 4.133 14.376 ;
     RECT  2.981 49.584 4.237 51.528 ;
     RECT  4.097 43.872 4.309 45.192 ;
     RECT  2.981 46.512 4.309 48.408 ;
     RECT  4.133 13.968 4.345 14.376 ;
     RECT  4.061 28.8 4.345 29.64 ;
     RECT  4.061 10.128 4.412 11.016 ;
     RECT  3.377 38.736 4.417 38.76 ;
     RECT  4.412 9.936 4.453 11.016 ;
     RECT  4.417 38.736 4.453 39.336 ;
     RECT  4.061 26.064 4.489 27.672 ;
     RECT  3.377 34.752 4.525 34.776 ;
     RECT  4.46 53.952 4.741 53.976 ;
     RECT  4.345 13.968 4.849 14.808 ;
     RECT  3.917 16.512 4.965 19.128 ;
     RECT  4.741 53.568 4.993 53.976 ;
     RECT  3.985 5.472 5.108 8.568 ;
     RECT  4.453 9.648 5.108 11.016 ;
     RECT  4.061 12.192 5.108 12.216 ;
     RECT  4.849 13.968 5.108 14.952 ;
     RECT  4.965 16.512 5.108 19.368 ;
     RECT  4.025 20.976 5.108 21 ;
     RECT  3.34 22.176 5.108 22.536 ;
     RECT  4.061 24.48 5.108 24.504 ;
     RECT  4.489 25.584 5.108 27.672 ;
     RECT  4.345 28.8 5.108 30.6 ;
     RECT  4.061 31.776 5.108 31.896 ;
     RECT  4.025 33.072 5.108 33.576 ;
     RECT  4.525 34.752 5.108 35.736 ;
     RECT  4.453 38.16 5.108 39.336 ;
     RECT  4.097 40.848 5.108 42.792 ;
     RECT  4.309 43.872 5.108 48.408 ;
     RECT  4.237 49.584 5.108 52.44 ;
     RECT  4.993 53.568 5.108 54.168 ;
     RECT  5.108 2.148 5.212 54.168 ;
     RECT  5.212 2.418 5.404 54.168 ;
     RECT  5.404 33.552 5.465 37.032 ;
     RECT  5.404 45.168 5.465 45.192 ;
     RECT  5.404 49.008 5.465 53.016 ;
     RECT  5.404 54.096 5.573 54.168 ;
     RECT  5.404 18.576 5.681 19.368 ;
     RECT  5.404 26.64 5.789 28.056 ;
     RECT  5.404 31.728 5.789 32.52 ;
     RECT  5.404 47.856 5.789 47.88 ;
     RECT  5.465 49.008 5.789 49.8 ;
     RECT  5.641 54.72 5.795 54.744 ;
     RECT  5.404 10.752 5.843 11.976 ;
     RECT  5.404 24.48 5.861 24.504 ;
     RECT  5.465 34.368 5.932 37.032 ;
     RECT  5.404 5.808 5.941 8.184 ;
     RECT  5.404 38.16 6.041 38.76 ;
     RECT  5.932 34.368 6.113 35.352 ;
     RECT  5.941 5.808 6.179 6.264 ;
     RECT  5.404 13.968 6.437 15.432 ;
     RECT  5.465 51.216 6.469 53.016 ;
     RECT  6.469 51.216 6.505 53.592 ;
     RECT  5.843 10.752 6.541 11.352 ;
     RECT  6.437 14.112 6.577 15.432 ;
     RECT  5.404 16.512 6.577 17.112 ;
     RECT  5.404 43.92 6.685 43.944 ;
     RECT  6.113 34.464 6.761 35.352 ;
     RECT  5.789 27.552 6.793 28.056 ;
     RECT  6.793 27.456 6.829 28.056 ;
     RECT  5.404 30.288 6.829 30.312 ;
     RECT  5.789 32.496 6.829 32.52 ;
     RECT  5.941 7.392 6.853 8.184 ;
     RECT  5.404 9.36 6.853 9.384 ;
     RECT  6.829 27.12 6.937 28.056 ;
     RECT  6.829 31.68 6.937 32.52 ;
     RECT  5.932 36.912 6.937 37.032 ;
     RECT  6.041 38.16 6.937 38.184 ;
     RECT  5.404 21.168 6.973 22.2 ;
     RECT  6.685 43.776 7.081 43.944 ;
     RECT  6.937 36.912 7.1 38.184 ;
     RECT  5.404 40.992 7.1 42.168 ;
     RECT  6.505 50.688 7.1 53.592 ;
     RECT  7.1 36.912 7.141 38.904 ;
     RECT  7.1 40.224 7.141 42.168 ;
     RECT  5.789 49.008 7.141 49.032 ;
     RECT  5.681 18.576 7.148 19.032 ;
     RECT  6.973 20.592 7.153 22.2 ;
     RECT  7.141 36.912 7.189 42.168 ;
     RECT  7.153 20.592 7.225 22.824 ;
     RECT  6.937 26.592 7.261 28.056 ;
     RECT  6.937 31.392 7.261 32.52 ;
     RECT  7.081 43.44 7.333 43.944 ;
     RECT  7.261 26.304 7.34 28.056 ;
     RECT  5.404 29.232 7.34 29.256 ;
     RECT  7.261 31.392 7.381 33.048 ;
     RECT  6.761 34.464 7.381 34.776 ;
     RECT  6.721 45.216 7.573 45.24 ;
     RECT  5.404 46.848 7.573 46.872 ;
     RECT  7.1 50.496 7.621 53.592 ;
     RECT  7.141 49.008 7.669 49.224 ;
     RECT  7.621 50.496 7.669 54.12 ;
     RECT  6.853 7.392 7.801 9.384 ;
     RECT  6.541 10.656 7.801 11.352 ;
     RECT  6.179 5.808 7.808 5.832 ;
     RECT  7.801 7.392 7.808 11.352 ;
     RECT  7.045 13.056 7.808 13.08 ;
     RECT  6.577 14.112 7.808 17.112 ;
     RECT  7.148 18.192 7.808 19.032 ;
     RECT  7.225 20.592 7.808 23.4 ;
     RECT  6.505 25.104 7.808 25.128 ;
     RECT  7.34 26.304 7.808 29.256 ;
     RECT  6.829 30.288 7.808 30.408 ;
     RECT  7.381 31.392 7.808 34.776 ;
     RECT  7.189 36 7.808 42.168 ;
     RECT  7.333 43.44 7.808 44.088 ;
     RECT  7.573 45.216 7.808 46.872 ;
     RECT  7.669 49.008 7.808 54.12 ;
     RECT  7.808 2.148 7.912 54.12 ;
     RECT  7.912 2.418 7.957 54.12 ;
     RECT  7.957 2.418 8.099 54.792 ;
     RECT  8.099 2.418 8.104 54.168 ;
     RECT  8.104 9.792 8.165 9.816 ;
     RECT  8.104 13.056 8.165 13.08 ;
     RECT  8.104 14.112 8.165 14.136 ;
     RECT  8.104 20.592 8.165 23.736 ;
     RECT  8.104 34.752 8.165 34.776 ;
     RECT  8.104 54.144 8.165 54.168 ;
     RECT  8.165 20.592 8.201 20.616 ;
     RECT  8.104 45.984 8.237 46.872 ;
     RECT  8.104 48.384 8.237 53.016 ;
     RECT  8.104 11.184 8.243 12.024 ;
     RECT  8.104 30.384 8.243 30.408 ;
     RECT  8.104 32.352 8.243 32.376 ;
     RECT  8.104 36 8.243 36.936 ;
     RECT  8.104 37.968 8.243 37.992 ;
     RECT  8.104 42 8.243 42.024 ;
     RECT  8.237 48.384 8.243 50.136 ;
     RECT  8.104 26.304 8.273 29.016 ;
     RECT  8.243 49.152 8.273 50.136 ;
     RECT  8.165 22.176 8.291 23.736 ;
     RECT  8.291 22.608 8.337 23.4 ;
     RECT  8.243 36 8.381 36.024 ;
     RECT  8.104 43.68 8.387 45 ;
     RECT  8.104 39.84 8.417 39.864 ;
     RECT  8.243 12 8.489 12.024 ;
     RECT  8.387 43.68 8.489 43.704 ;
     RECT  8.337 22.608 8.561 22.632 ;
     RECT  8.104 15.984 8.777 16.392 ;
     RECT  8.237 45.984 8.813 46.776 ;
     RECT  8.237 51.36 8.813 53.016 ;
     RECT  8.809 0.528 8.963 0.552 ;
     RECT  8.777 16.272 8.993 16.392 ;
     RECT  8.813 51.936 9.011 53.016 ;
     RECT  8.273 49.2 9.205 50.136 ;
     RECT  9.205 53.568 9.445 53.592 ;
     RECT  9.011 51.936 9.973 52.584 ;
     RECT  9.445 53.568 9.973 53.64 ;
     RECT  8.273 26.304 10.357 28.344 ;
     RECT  9.973 51.936 10.357 53.64 ;
     RECT  10.357 51.936 10.499 54.168 ;
     RECT  8.104 8.16 10.508 8.472 ;
     RECT  10.357 26.304 10.508 28.44 ;
     RECT  8.813 46.752 10.508 46.776 ;
     RECT  9.205 49.2 10.508 50.328 ;
     RECT  10.499 51.936 10.508 54.12 ;
     RECT  10.508 2.148 10.612 54.12 ;
     RECT  10.612 2.418 10.739 54.12 ;
     RECT  10.739 2.418 10.804 53.742 ;
     RECT  10.804 26.496 11.261 29.016 ;
     RECT  10.804 49.2 11.621 50.712 ;
     RECT  10.804 52.992 11.747 53.688 ;
     RECT  11.747 52.992 11.869 53.592 ;
     RECT  11.621 49.2 11.945 50.136 ;
     RECT  11.869 52.8 11.987 53.592 ;
     RECT  10.804 46.752 12.133 46.776 ;
     RECT  10.804 8.448 12.265 8.472 ;
     RECT  12.085 51.744 12.733 51.768 ;
     RECT  12.733 50.88 12.949 51.768 ;
     RECT  11.987 52.848 12.949 53.592 ;
     RECT  11.945 49.2 13.021 49.848 ;
     RECT  12.949 50.88 13.021 53.592 ;
     RECT  13.021 49.2 13.057 53.592 ;
     RECT  12.265 8.16 13.208 8.472 ;
     RECT  11.261 26.496 13.208 28.68 ;
     RECT  12.133 46.752 13.208 47.256 ;
     RECT  13.057 49.008 13.208 53.592 ;
     RECT  13.129 55.296 13.235 55.32 ;
     RECT  13.208 2.148 13.312 54.012 ;
     RECT  13.312 2.418 13.429 54.012 ;
     RECT  13.429 2.418 13.504 54.12 ;
     RECT  13.504 26.592 13.565 28.104 ;
     RECT  13.504 49.008 13.619 54.12 ;
     RECT  13.619 49.008 13.709 53.592 ;
     RECT  13.709 49.008 13.889 51.768 ;
     RECT  13.889 50.736 13.961 51.768 ;
     RECT  13.709 52.848 13.997 53.592 ;
     RECT  13.997 52.992 14.257 53.592 ;
     RECT  13.565 26.88 14.497 28.104 ;
     RECT  14.257 53.568 14.723 53.592 ;
     RECT  14.497 26.88 14.821 28.2 ;
     RECT  13.504 46.752 14.821 46.776 ;
     RECT  14.821 46.752 14.861 46.872 ;
     RECT  13.961 50.928 15.164 51.768 ;
     RECT  13.889 49.008 15.361 49.608 ;
     RECT  15.164 50.928 15.361 52.584 ;
     RECT  15.361 50.928 15.505 53.016 ;
     RECT  15.361 49.008 15.781 49.848 ;
     RECT  15.505 50.88 15.781 53.016 ;
     RECT  14.885 54.096 15.781 54.12 ;
     RECT  13.504 8.16 15.908 8.184 ;
     RECT  14.821 26.88 15.908 28.44 ;
     RECT  14.861 46.848 15.908 46.872 ;
     RECT  15.781 49.008 15.908 53.016 ;
     RECT  15.781 54.096 15.908 54.168 ;
     RECT  15.908 2.148 15.971 54.168 ;
     RECT  15.971 2.148 16.012 54.12 ;
     RECT  16.012 2.418 16.204 54.12 ;
     RECT  16.204 53.568 16.301 54.12 ;
     RECT  16.301 53.568 16.499 54.072 ;
     RECT  16.204 49.008 16.517 52.44 ;
     RECT  16.499 53.568 16.913 53.64 ;
     RECT  16.913 53.568 17.941 53.592 ;
     RECT  17.941 52.848 18.469 53.592 ;
     RECT  16.204 8.16 18.608 8.184 ;
     RECT  16.204 26.88 18.608 28.248 ;
     RECT  16.204 46.848 18.608 46.872 ;
     RECT  16.517 49.008 18.608 51.768 ;
     RECT  18.469 52.8 18.608 53.592 ;
     RECT  18.469 54.672 18.608 54.696 ;
     RECT  18.608 2.148 18.707 54.696 ;
     RECT  18.707 2.148 18.712 54.12 ;
     RECT  18.712 2.418 18.904 54.12 ;
     RECT  18.904 49.008 19.043 54.12 ;
     RECT  19.043 49.008 19.397 53.64 ;
     RECT  18.904 27.456 19.469 28.296 ;
     RECT  19.469 27.696 19.505 28.296 ;
     RECT  19.397 52.272 19.955 53.64 ;
     RECT  19.955 52.272 20.473 53.016 ;
     RECT  19.505 27.696 20.689 28.2 ;
     RECT  19.397 49.008 20.917 51.192 ;
     RECT  20.473 52.176 20.917 53.016 ;
     RECT  20.917 49.008 21.013 53.016 ;
     RECT  21.013 49.008 21.193 53.064 ;
     RECT  18.904 8.16 21.308 8.184 ;
     RECT  20.689 27.696 21.308 28.68 ;
     RECT  18.904 46.848 21.308 46.872 ;
     RECT  21.193 48.912 21.308 53.064 ;
     RECT  21.109 54.144 21.308 54.168 ;
     RECT  21.308 2.148 21.412 54.168 ;
     RECT  21.412 2.418 21.443 54.168 ;
     RECT  21.443 2.418 21.604 53.742 ;
     RECT  21.604 27.888 22.277 27.912 ;
     RECT  21.604 44.4 22.385 44.424 ;
     RECT  21.604 43.344 22.597 43.368 ;
     RECT  21.604 49.2 22.601 53.592 ;
     RECT  22.597 42.96 22.633 43.368 ;
     RECT  22.633 42.864 22.813 43.368 ;
     RECT  22.813 42.672 22.817 43.368 ;
     RECT  22.601 53.568 22.885 53.592 ;
     RECT  21.604 46.752 22.921 46.872 ;
     RECT  22.817 42.672 22.925 42.792 ;
     RECT  23.317 55.296 23.459 55.32 ;
     RECT  22.601 49.2 23.713 52.296 ;
     RECT  22.885 53.568 23.852 53.64 ;
     RECT  23.713 49.056 23.929 52.296 ;
     RECT  21.604 8.16 24.008 8.184 ;
     RECT  22.849 45.024 24.008 45.048 ;
     RECT  22.921 46.752 24.008 46.92 ;
     RECT  23.929 48.144 24.008 52.296 ;
     RECT  23.852 53.568 24.008 53.736 ;
     RECT  24.008 2.148 24.112 54.012 ;
     RECT  24.112 2.418 24.133 54.012 ;
     RECT  24.133 2.418 24.304 54.168 ;
     RECT  24.304 52.224 24.365 54.168 ;
     RECT  24.365 52.224 24.437 53.592 ;
     RECT  24.437 52.272 24.947 53.592 ;
     RECT  24.304 49.008 25.621 51.24 ;
     RECT  24.947 52.272 25.621 53.064 ;
     RECT  25.621 49.008 25.909 53.064 ;
     RECT  25.621 54.096 25.909 54.12 ;
     RECT  25.909 49.008 26.533 54.12 ;
     RECT  26.533 49.008 26.675 54.168 ;
     RECT  26.593 46.704 26.701 46.728 ;
     RECT  24.304 8.16 26.708 8.184 ;
     RECT  25.909 26.736 26.708 26.76 ;
     RECT  26.701 46.704 26.708 46.872 ;
     RECT  26.675 49.008 26.708 54.12 ;
     RECT  26.708 2.148 26.812 54.12 ;
     RECT  26.812 2.418 27.004 54.12 ;
     RECT  27.004 46.848 27.065 46.872 ;
     RECT  27.004 49.488 27.155 54.12 ;
     RECT  27.155 49.488 27.389 53.64 ;
     RECT  27.389 49.488 27.971 52.296 ;
     RECT  27.389 53.568 28.405 53.64 ;
     RECT  27.971 49.584 29.125 52.296 ;
     RECT  28.405 53.568 29.125 53.688 ;
     RECT  29.125 49.584 29.269 53.688 ;
     RECT  27.004 8.16 29.408 8.184 ;
     RECT  29.269 49.584 29.408 54.168 ;
     RECT  29.408 2.148 29.411 54.168 ;
     RECT  29.411 2.148 29.512 54.12 ;
     RECT  29.512 2.418 29.704 54.12 ;
     RECT  29.704 49.584 29.873 54.12 ;
     RECT  29.873 49.584 29.909 53.64 ;
     RECT  29.704 46.752 30.413 46.776 ;
     RECT  29.909 49.776 30.629 53.64 ;
     RECT  30.629 49.776 30.701 52.584 ;
     RECT  30.701 52.224 30.737 52.584 ;
     RECT  30.737 52.224 31.861 52.296 ;
     RECT  30.629 53.568 31.861 53.64 ;
     RECT  31.861 52.224 31.957 53.64 ;
     RECT  29.704 8.16 32.108 8.184 ;
     RECT  32.065 46.752 32.108 46.776 ;
     RECT  30.701 49.776 32.108 51.24 ;
     RECT  31.957 52.224 32.108 54.168 ;
     RECT  32.108 2.148 32.147 54.168 ;
     RECT  32.147 2.148 32.212 54.12 ;
     RECT  32.212 2.418 32.404 54.12 ;
     RECT  32.404 46.8 32.465 46.824 ;
     RECT  32.404 49.872 32.476 54.12 ;
     RECT  32.476 49.872 34.325 53.592 ;
     RECT  32.404 8.16 34.808 8.184 ;
     RECT  34.765 48.432 34.808 48.456 ;
     RECT  34.325 49.872 34.808 54.12 ;
     RECT  34.808 2.148 34.837 54.12 ;
     RECT  34.837 2.148 34.912 54.168 ;
     RECT  34.912 2.418 35.104 54.168 ;
     RECT  35.104 49.68 35.125 54.168 ;
     RECT  35.125 49.68 35.212 54.264 ;
     RECT  35.212 49.68 35.219 54.168 ;
     RECT  35.219 49.68 35.705 52.584 ;
     RECT  35.104 3.456 35.843 3.48 ;
     RECT  35.104 8.16 35.843 8.184 ;
     RECT  35.219 53.568 36.313 53.592 ;
     RECT  36.277 49.008 36.389 49.032 ;
     RECT  36.313 53.568 36.419 54.12 ;
     RECT  35.705 50.112 36.421 52.584 ;
     RECT  36.419 53.568 36.421 53.592 ;
     RECT  36.349 1.728 36.467 1.752 ;
     RECT  36.421 50.112 37.508 53.592 ;
     RECT  37.508 2.148 37.573 54.012 ;
     RECT  37.573 2.148 37.612 54.168 ;
     RECT  37.612 2.418 37.804 54.168 ;
     RECT  37.804 50.256 37.973 54.168 ;
     RECT  37.973 50.256 38.003 54.12 ;
     RECT  38.003 50.256 38.837 53.592 ;
     RECT  38.837 50.352 39.808 53.592 ;
     RECT  39.808 50.352 40.208 53.64 ;
     RECT  40.208 2.148 40.301 54.012 ;
     RECT  40.301 2.148 40.312 54.168 ;
     RECT  40.312 2.418 40.385 54.168 ;
     RECT  40.385 2.418 40.504 54.12 ;
     RECT  40.504 50.352 40.565 51.192 ;
     RECT  40.565 50.352 41.357 51.144 ;
     RECT  41.357 50.352 41.429 50.376 ;
     RECT  40.504 52.416 41.429 54.12 ;
     RECT  41.429 52.416 41.465 52.44 ;
     RECT  41.429 54.096 42.185 54.12 ;
     RECT  42.908 2.148 43.012 54.012 ;
     RECT  43.012 2.418 43.204 53.742 ;
    LAYER M5 ;
     RECT  2.4 2.137 2.52 2.151 ;
     RECT  5.1 2.137 5.22 2.151 ;
     RECT  7.8 2.137 7.92 2.151 ;
     RECT  8.928 0.517 8.952 2.151 ;
     RECT  10.5 2.137 10.62 2.151 ;
     RECT  13.2 2.137 13.32 2.151 ;
     RECT  15.9 2.137 16.02 2.151 ;
     RECT  18.096 2.137 18.72 2.151 ;
     RECT  21.3 2.137 21.42 2.151 ;
     RECT  24 2.137 24.12 2.151 ;
     RECT  26.7 2.137 26.82 2.151 ;
     RECT  29.4 2.137 29.52 2.151 ;
     RECT  32.1 2.137 32.22 2.151 ;
     RECT  34.8 2.137 34.92 2.151 ;
     RECT  37.5 2.137 37.62 2.151 ;
     RECT  40.2 2.137 40.32 2.151 ;
     RECT  42.9 2.137 43.02 2.151 ;
     RECT  34.8 2.151 35.112 3.445 ;
     RECT  2.4 2.151 2.712 4.501 ;
     RECT  2.4 4.501 2.808 5.459 ;
     RECT  5.1 2.151 5.412 6.133 ;
     RECT  5.1 6.133 5.928 6.229 ;
     RECT  5.1 6.229 6.168 7.381 ;
     RECT  7.8 2.151 8.952 7.381 ;
     RECT  5.1 7.381 8.952 7.909 ;
     RECT  4.32 7.909 8.952 8.195 ;
     RECT  34.8 3.445 35.832 8.195 ;
     RECT  6.864 8.195 8.952 8.483 ;
     RECT  4.32 8.195 5.832 8.579 ;
     RECT  5.1 8.579 5.832 9.925 ;
     RECT  4.464 9.925 5.832 11.027 ;
     RECT  3.984 13.045 4.008 14.387 ;
     RECT  5.1 11.027 5.832 15.443 ;
     RECT  7.8 8.483 8.952 15.733 ;
     RECT  5.1 15.443 5.412 16.501 ;
     RECT  5.1 16.501 5.88 17.123 ;
     RECT  2.4 5.459 2.712 18.181 ;
     RECT  5.1 17.123 5.412 18.181 ;
     RECT  7.68 15.733 8.952 18.181 ;
     RECT  2.4 18.181 3.432 18.851 ;
     RECT  4.992 18.181 5.412 19.379 ;
     RECT  2.4 18.851 2.712 21.493 ;
     RECT  2.4 21.493 3.288 23.411 ;
     RECT  5.1 19.379 5.412 25.573 ;
     RECT  4.56 25.573 5.412 26.387 ;
     RECT  26.7 2.151 27.012 26.725 ;
     RECT  18.096 2.151 18.912 26.915 ;
     RECT  7.2 18.181 8.952 27.301 ;
     RECT  13.2 2.151 13.512 27.541 ;
     RECT  13.2 27.541 13.608 27.779 ;
     RECT  2.4 23.411 2.712 27.877 ;
     RECT  2.4 27.877 3.336 28.835 ;
     RECT  6.96 27.301 8.952 31.669 ;
     RECT  6.864 31.669 8.952 32.531 ;
     RECT  1.152 32.917 1.176 33.059 ;
     RECT  3.984 31.861 4.008 33.107 ;
     RECT  5.1 26.387 5.412 35.317 ;
     RECT  5.1 35.317 5.88 36.275 ;
     RECT  6.96 32.531 8.952 37.667 ;
     RECT  7.152 37.667 8.952 41.123 ;
     RECT  5.1 36.275 5.412 44.437 ;
     RECT  7.584 41.123 8.952 46.019 ;
     RECT  13.2 27.779 13.512 47.221 ;
     RECT  4.32 44.437 5.412 47.363 ;
     RECT  24 2.151 24.312 48.997 ;
     RECT  25.92 26.725 27.012 48.997 ;
     RECT  7.68 46.019 8.952 49.189 ;
     RECT  12.144 47.221 13.512 49.235 ;
     RECT  24 48.997 27.012 49.235 ;
     RECT  7.152 49.189 8.952 49.331 ;
     RECT  25.92 49.235 27.012 49.477 ;
     RECT  15.9 2.151 16.212 49.573 ;
     RECT  29.4 2.151 29.712 49.573 ;
     RECT  7.152 49.331 8.232 49.619 ;
     RECT  12.144 49.235 12.168 49.811 ;
     RECT  20.208 49.477 20.232 49.861 ;
     RECT  21.3 2.151 21.612 49.861 ;
     RECT  25.92 49.477 27.96 50.005 ;
     RECT  29.088 49.573 29.712 50.005 ;
     RECT  25.92 50.005 29.712 50.051 ;
     RECT  26.7 50.051 29.712 50.147 ;
     RECT  3.984 50.005 4.008 50.243 ;
     RECT  20.208 49.861 21.612 50.243 ;
     RECT  15.792 49.573 16.212 50.435 ;
     RECT  7.152 49.619 8.112 50.531 ;
     RECT  7.68 50.531 8.112 50.867 ;
     RECT  28.416 50.147 29.712 51.347 ;
     RECT  21.072 50.243 21.612 52.021 ;
     RECT  7.8 50.867 8.112 52.549 ;
     RECT  10.5 2.151 10.812 52.549 ;
     RECT  13.2 49.235 13.512 52.549 ;
     RECT  15.9 50.435 16.212 52.549 ;
     RECT  20.928 52.021 21.612 52.549 ;
     RECT  26.7 50.147 27.012 52.549 ;
     RECT  29.4 51.347 29.712 52.549 ;
     RECT  32.1 2.151 32.412 52.549 ;
     RECT  34.8 8.195 35.112 52.549 ;
     RECT  37.5 2.151 37.812 52.549 ;
     RECT  7.8 52.549 8.76 52.597 ;
     RECT  26.544 52.549 27.012 52.693 ;
     RECT  18.6 26.915 18.912 52.741 ;
     RECT  20.16 52.549 21.612 52.741 ;
     RECT  29.4 52.549 30.648 52.741 ;
     RECT  18.6 52.741 22.2 52.789 ;
     RECT  24 49.235 24.312 52.789 ;
     RECT  26.544 52.693 27.144 52.789 ;
     RECT  29.28 52.741 30.648 52.789 ;
     RECT  31.968 52.549 32.412 52.789 ;
     RECT  37.5 52.549 38.616 52.789 ;
     RECT  5.1 47.363 5.412 52.837 ;
     RECT  7.8 52.597 9 52.837 ;
     RECT  11.952 52.789 11.976 52.837 ;
     RECT  12.96 52.549 13.512 52.837 ;
     RECT  18.48 52.789 22.2 52.837 ;
     RECT  10.224 52.549 10.812 52.981 ;
     RECT  11.952 52.837 13.608 52.981 ;
     RECT  36.864 52.789 38.616 52.981 ;
     RECT  40.2 2.151 40.512 52.981 ;
     RECT  24 52.789 25.176 53.029 ;
     RECT  26.16 52.789 27.144 53.029 ;
     RECT  5.1 52.837 9 53.557 ;
     RECT  9.984 52.981 14.232 53.557 ;
     RECT  15.216 52.549 16.212 53.557 ;
     RECT  17.952 52.837 22.2 53.557 ;
     RECT  24 53.029 27.144 53.557 ;
     RECT  29.136 52.789 30.648 53.557 ;
     RECT  31.872 52.789 32.76 53.557 ;
     RECT  33.888 52.549 35.88 53.557 ;
     RECT  36.864 52.981 40.512 53.557 ;
     RECT  4.752 53.557 22.68 53.605 ;
     RECT  24 53.557 40.632 53.605 ;
     RECT  4.752 53.605 40.632 53.941 ;
     RECT  2.4 28.835 2.712 54.009 ;
     RECT  42.9 2.151 43.212 54.009 ;
     RECT  2.4 54.009 2.52 54.023 ;
     RECT  42.9 54.009 43.02 54.023 ;
     RECT  4.512 53.941 40.632 54.085 ;
     RECT  4.512 54.085 40.872 56.016 ;
     RECT  7.92 2.137 8.928 2.151 ;
     RECT  5.832 8.195 6.864 8.483 ;
     RECT  4.464 8.579 5.1 9.925 ;
     RECT  2.712 13.045 3.984 14.387 ;
     RECT  4.008 13.045 5.1 14.387 ;
     RECT  5.412 15.443 5.832 16.501 ;
     RECT  5.412 31.669 6.864 32.531 ;
     RECT  2.712 31.861 3.984 33.107 ;
     RECT  4.008 31.861 5.1 33.107 ;
     RECT  1.176 32.917 2.4 33.059 ;
     RECT  5.88 35.317 6.96 36.275 ;
     RECT  10.812 47.221 12.144 49.811 ;
     RECT  12.168 49.235 13.2 49.811 ;
     RECT  18.912 49.477 20.208 50.243 ;
     RECT  20.232 49.477 21.3 49.861 ;
     RECT  27.96 49.477 29.4 49.573 ;
     RECT  27.96 49.573 29.088 50.005 ;
     RECT  2.712 50.005 3.984 50.243 ;
     RECT  4.008 50.005 5.1 50.243 ;
     RECT  27.012 50.147 28.416 51.347 ;
     RECT  27.012 51.347 27.144 52.693 ;
     RECT  29.136 51.347 29.4 52.741 ;
     RECT  8.76 52.549 10.224 52.597 ;
     RECT  18.912 52.549 20.16 52.741 ;
     RECT  30.648 52.549 31.968 52.789 ;
     RECT  32.412 52.549 33.888 52.789 ;
     RECT  9 52.597 10.224 52.981 ;
     RECT  29.136 52.741 29.28 52.789 ;
     RECT  10.812 52.789 11.952 52.981 ;
     RECT  11.976 52.789 12.96 52.837 ;
     RECT  25.176 52.789 26.16 53.029 ;
     RECT  30.648 52.789 31.872 53.557 ;
     RECT  32.76 52.789 33.888 53.557 ;
     RECT  35.88 52.789 36.864 53.557 ;
     RECT  9 52.981 9.984 53.557 ;
     RECT  14.232 52.981 15.216 53.557 ;
     RECT  22.68 53.557 24 53.605 ;
  END
END dsfd_l2r_vc_291x1__hs_hwSW
END LIBRARY
